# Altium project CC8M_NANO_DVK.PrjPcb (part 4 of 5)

## Sheet 18 - I2C, XBee.SchDoc: I2C, XBee
size A3; PageSetup: Record=PageOptions¦CenterHorizontal=True¦CenterVertical=True¦PrintScale=0.70¦XCorrection=1.00¦YCorrection=1.00¦PrintKind=0¦BorderSize=5000000¦LeftOffset=0¦BottomOffset=0¦Orientation=2¦PaperLength=4200¦PaperWidth=2970¦Scale=100¦PaperSource=7¦PrintQuality=600¦MediaType=1¦DitherType=10¦PaperKind=A4¦PrintScaleMode=1; Author: Juan Anzola; SheetNumber: 18; SheetTotal: 21

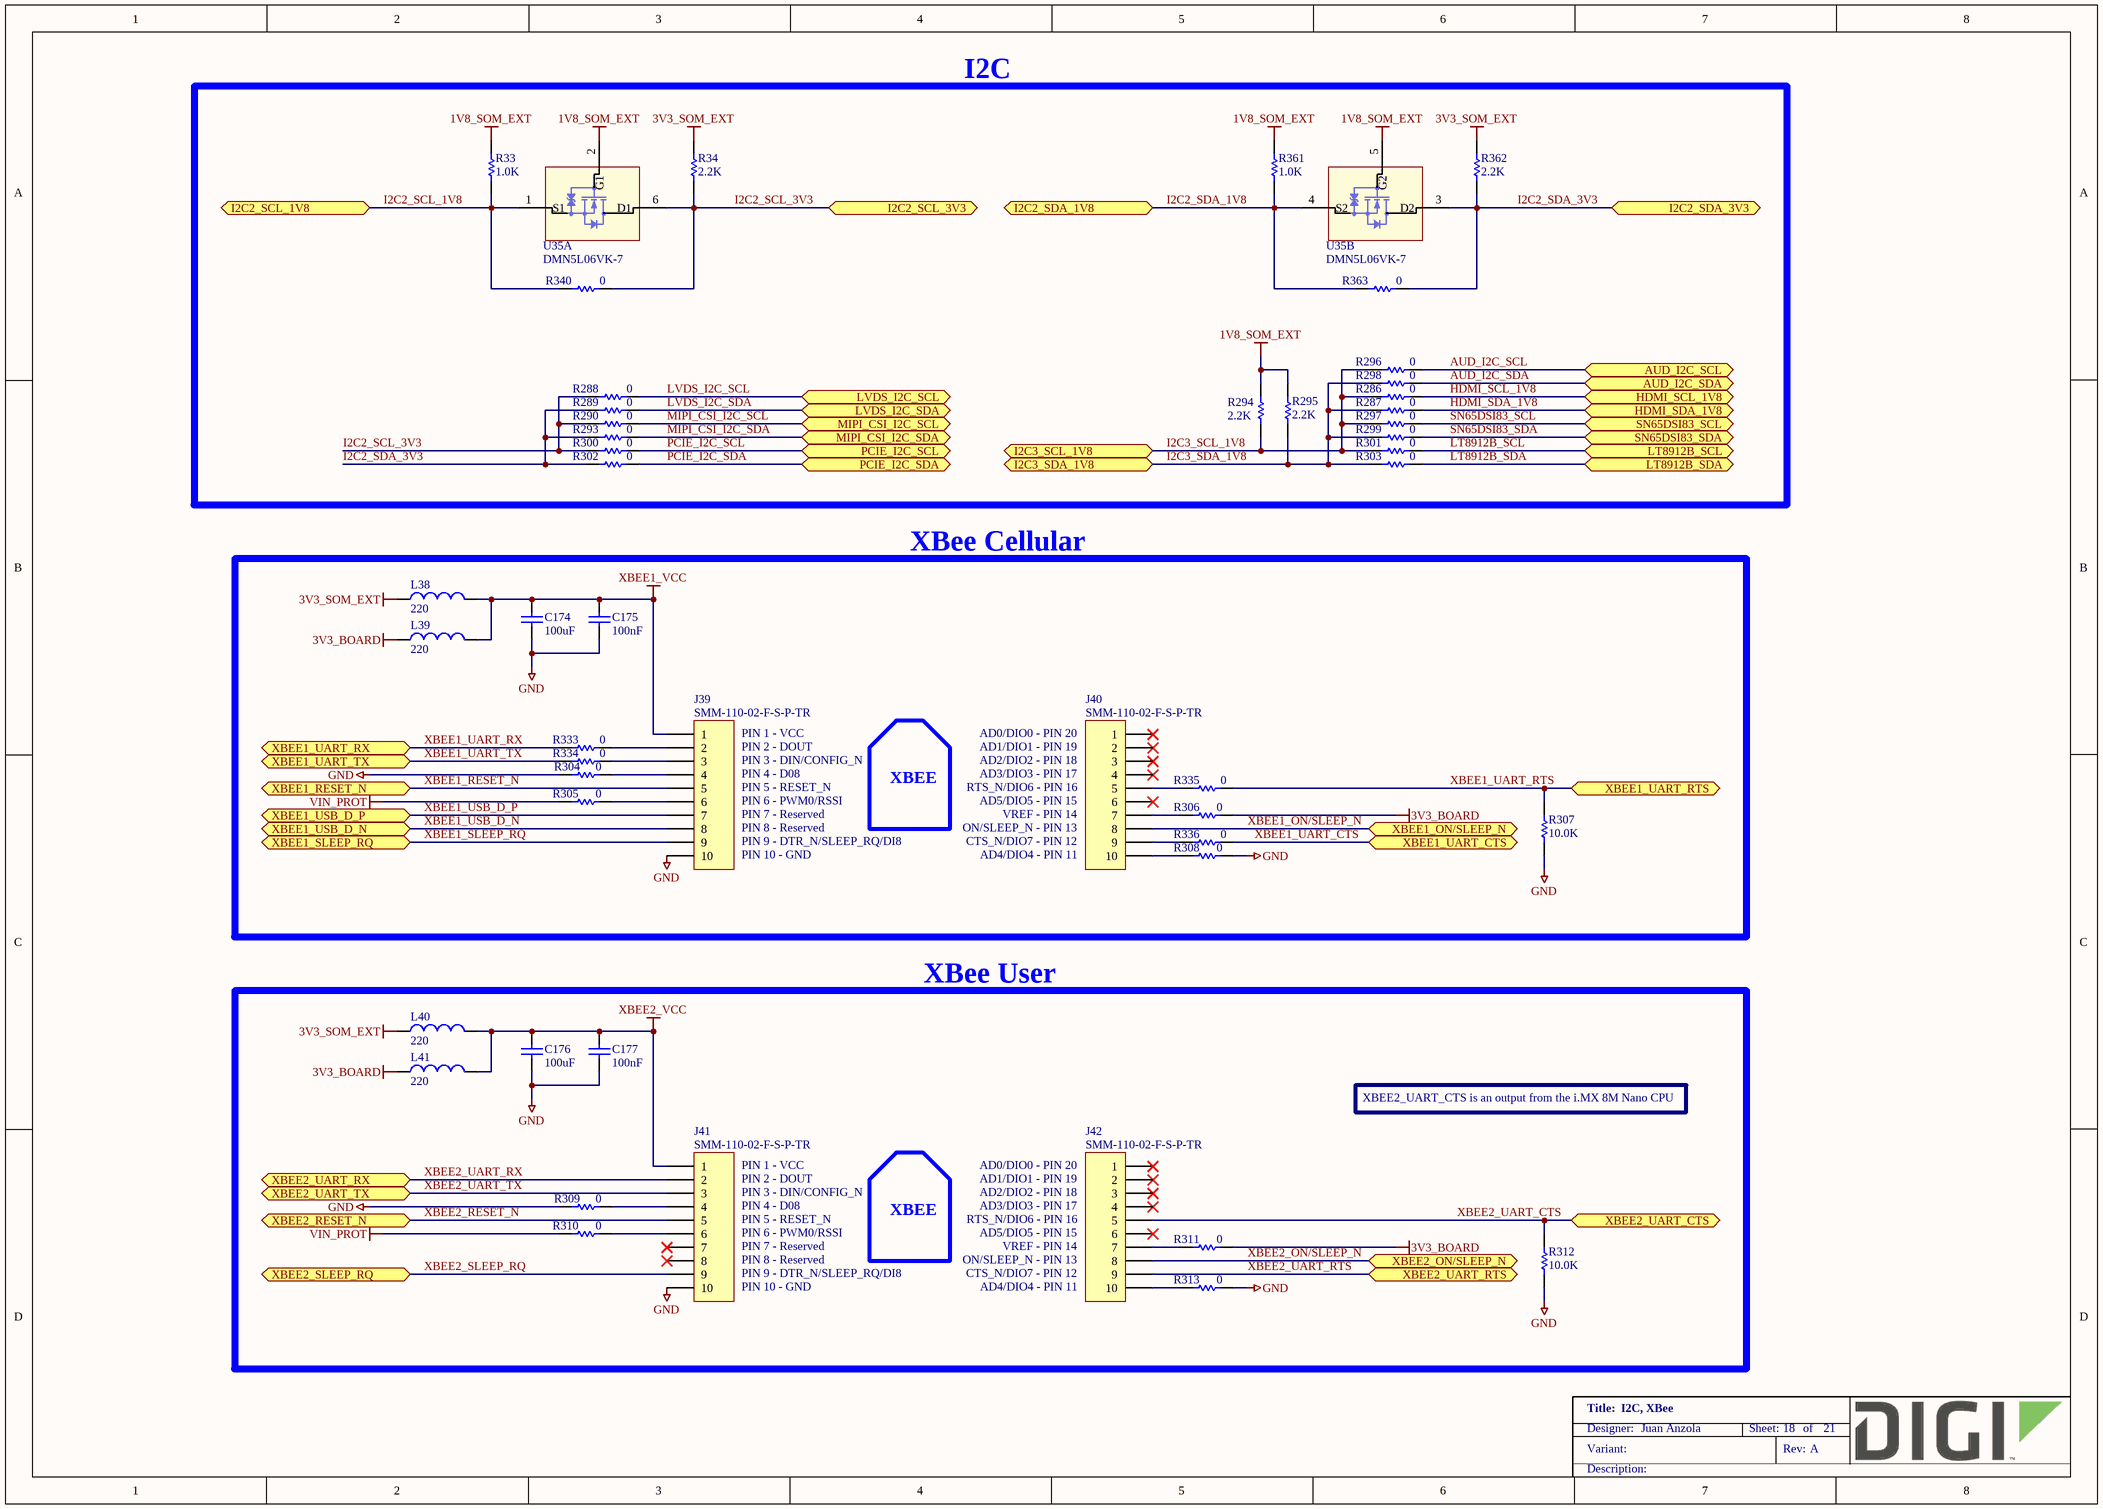
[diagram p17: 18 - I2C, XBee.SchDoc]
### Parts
C174  100uF  [CAPC3216X190N]
C175  100nF  [CAPC1005X55N]
C176  100uF  [CAPC3216X190N]
C177  100nF  [CAPC1005X55N]
J39  SMM-110-02-F-S-P-TR  [Samtec_SMM-110-02-F-S]
J40  SMM-110-02-F-S-P-TR  [Samtec_SMM-110-02-F-S]
J41  SMM-110-02-F-S-P-TR  [Samtec_SMM-110-02-F-S]
J42  SMM-110-02-F-S-P-TR  [Samtec_SMM-110-02-F-S]
L38  220  [INDC2013X110N]
L39  220  [INDC2013X110N]
L40  220  [INDC2013X110N]
L41  220  [INDC2013X110N]
R33  1.0K  [RESC1005X40N]
R34  2.2K  [RESC1005X40N]
R286  0  [RESC1005X40N]
R287  0  [RESC1005X40N]
R288  0  [RESC1005X40N]
R289  0  [RESC1005X40N]
R290  0  [RESC1005X40N]
R293  0  [RESC1005X40N]
R294  2.2K  [RESC1005X40N]
R295  2.2K  [RESC1005X40N]
R296  0  [RESC1005X40N]
R297  0  [RESC1005X40N]
R298  0  [RESC1005X40N]
R299  0  [RESC1005X40N]
R300  0  [RESC1005X40N]
R301  0  [RESC1005X40N]
R302  0  [RESC1005X40N]
R303  0  [RESC1005X40N]
R304  0  [RESC1005X40N]
R305  0  [RESC1005X40N]
R306  0  [RESC1005X40N]
R307  10.0K  [RESC1005X40N]
R308  0  [RESC1005X40N]
R309  0  [RESC1005X40N]
R310  0  [RESC1005X40N]
R311  0  [RESC1005X40N]
R312  10.0K  [RESC1005X40N]
R313  0  [RESC1005X40N]
R333  0  [RESC1005X40N]
R334  0  [RESC1005X40N]
R335  0  [RESC1005X40N]
R336  0  [RESC1005X40N]
R340  0  [RESC1005X40N]
R361  1.0K  [RESC1005X40N]
R362  2.2K  [RESC1005X40N]
R363  0  [RESC1005X40N]
U35  DMN5L06VK-7  [SOTFL50P160X60-6N]  (parts A,B of 2)

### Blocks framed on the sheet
I2C: R33 R34 R286-R290 R293-R303 R340 R361-R363 U35
XBee Cellular: C174 C175 J39 J40 L38 L39 R304-R308 R333-R336
XBee User: C176 C177 J41 J42 L40 L41 R309-R313

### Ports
AUD_I2C_SCL (bidir), AUD_I2C_SDA (bidir), HDMI_SCL_1V8 (bidir), HDMI_SDA_1V8 (bidir), I2C2_SCL_1V8 (bidir), I2C2_SCL_3V3 (bidir), I2C2_SDA_1V8 (bidir), I2C2_SDA_3V3 (bidir), I2C3_SCL_1V8 (bidir), I2C3_SDA_1V8 (bidir), LT8912B_SCL (bidir), LT8912B_SDA (bidir), LVDS_I2C_SCL (bidir), LVDS_I2C_SDA (bidir), MIPI_CSI_I2C_SCL (bidir), MIPI_CSI_I2C_SDA (bidir), PCIE_I2C_SCL (bidir), PCIE_I2C_SDA (bidir), SN65DSI83_SCL (bidir), SN65DSI83_SDA (bidir), XBEE1_ON/SLEEP_N (bidir), XBEE1_RESET_N (bidir), XBEE1_SLEEP_RQ (bidir), XBEE1_UART_CTS (bidir), XBEE1_UART_RTS (bidir), XBEE1_UART_RX (bidir), XBEE1_UART_TX (bidir), XBEE1_USB_D_N (bidir), XBEE1_USB_D_P (bidir), XBEE2_ON/SLEEP_N (bidir), XBEE2_RESET_N (bidir), XBEE2_SLEEP_RQ (bidir), XBEE2_UART_CTS (bidir), XBEE2_UART_RTS (bidir), XBEE2_UART_RX (bidir), XBEE2_UART_TX (bidir)

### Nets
1V8_SOM_EXT: R33.2 R294.2 R295.2 R361.2 U35.2(G1) U35.5(G2)
3V3_BOARD: L39.1 L41.1 R306.2 R311.2
3V3_SOM_EXT: L38.1 L40.1 R34.2 R362.2
GND: C174.1 C175.1 C176.1 C177.1 J39.10 J41.10 R304.1 R307.1 R308.2 R309.1 R312.1 R313.2
VIN_PROT: R305.1 R310.1
XBEE1_VCC: C174.2 C175.2 J39.1 L38.2 L39.2
XBEE2_VCC: C176.2 C177.2 J41.1 L40.2 L41.2
AUD_I2C_SCL: R296.2 ; port AUD_I2C_SCL
AUD_I2C_SDA: R298.2 ; port AUD_I2C_SDA
HDMI_SCL_1V8: R286.2 ; port HDMI_SCL_1V8
HDMI_SDA_1V8: R287.2 ; port HDMI_SDA_1V8
I2C2_SCL_1V8: R33.1 R340.1 U35.1(S1) ; port I2C2_SCL_1V8
I2C2_SCL_3V3: R34.1 R288.1 R290.1 R300.1 R340.2 U35.6(D1) ; port I2C2_SCL_3V3
I2C2_SDA_1V8: R361.1 R363.1 U35.4(S2) ; port I2C2_SDA_1V8
I2C2_SDA_3V3: R289.1 R293.1 R302.1 R362.1 R363.2 U35.3(D2) ; port I2C2_SDA_3V3
I2C3_SCL_1V8: R286.1 R294.1 R296.1 R297.1 R301.1 ; port I2C3_SCL_1V8
I2C3_SDA_1V8: R287.1 R295.1 R298.1 R299.1 R303.1 ; port I2C3_SDA_1V8
LT8912B_SCL: R301.2 ; port LT8912B_SCL
LT8912B_SDA: R303.2 ; port LT8912B_SDA
LVDS_I2C_SCL: R288.2 ; port LVDS_I2C_SCL
LVDS_I2C_SDA: R289.2 ; port LVDS_I2C_SDA
MIPI_CSI_I2C_SCL: R290.2 ; port MIPI_CSI_I2C_SCL
MIPI_CSI_I2C_SDA: R293.2 ; port MIPI_CSI_I2C_SDA
PCIE_I2C_SCL: R300.2 ; port PCIE_I2C_SCL
PCIE_I2C_SDA: R302.2 ; port PCIE_I2C_SDA
SN65DSI83_SCL: R297.2 ; port SN65DSI83_SCL
SN65DSI83_SDA: R299.2 ; port SN65DSI83_SDA
XBEE1_ON/SLEEP_N: J40.8 ; port XBEE1_ON/SLEEP_N
XBEE1_RESET_N: J39.5 ; port XBEE1_RESET_N
XBEE1_SLEEP_RQ: J39.9 ; port XBEE1_SLEEP_RQ
XBEE1_UART_CTS: R336.2 ; port XBEE1_UART_CTS
XBEE1_UART_RTS: R307.2 R335.2 ; port XBEE1_UART_RTS
XBEE1_UART_RX: R333.1 ; port XBEE1_UART_RX
XBEE1_UART_TX: R334.1 ; port XBEE1_UART_TX
XBEE1_USB_D_N: J39.8 ; port XBEE1_USB_D_N
XBEE1_USB_D_P: J39.7 ; port XBEE1_USB_D_P
XBEE2_ON/SLEEP_N: J42.8 ; port XBEE2_ON/SLEEP_N
XBEE2_RESET_N: J41.5 ; port XBEE2_RESET_N
XBEE2_SLEEP_RQ: J41.9 ; port XBEE2_SLEEP_RQ
XBEE2_UART_CTS: J42.5 R312.2 ; port XBEE2_UART_CTS
XBEE2_UART_RTS: J42.9 ; port XBEE2_UART_RTS
XBEE2_UART_RX: J41.2 ; port XBEE2_UART_RX
XBEE2_UART_TX: J41.3 ; port XBEE2_UART_TX
NetJ39_2: J39.2 R333.2
NetJ39_3: J39.3 R334.2
NetJ39_4: J39.4 R304.2
NetJ39_6: J39.6 R305.2
NetJ40_5: J40.5 R335.1
NetJ40_7: J40.7 R306.1
NetJ40_9: J40.9 R336.1
NetJ40_10: J40.10 R308.1
NetJ41_4: J41.4 R309.2
NetJ41_6: J41.6 R310.2
NetJ42_7: J42.7 R311.1
NetJ42_10: J42.10 R313.1

Not connected (* = marked no-connect by the designer): J40 1* 2* 3* 4* 6*; J41 7* 8*; J42 1* 2* 3* 4* 6*

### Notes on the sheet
- (near J39) PIN 1 - VCC
- (near J39) PIN 2 - DOUT
- (near J39) PIN 3 - DIN/CONFIG_N
- (near J39) PIN 4 - D08
- XBEE
- (near J40) AD0/DIO0 - PIN 20
- (near J40) AD1/DIO1 - PIN 19
- (near J40) AD2/DIO2 - PIN 18
- (near J40) AD3/DIO3 - PIN 17
- (near J39) PIN 5 - RESET_N
- (near J39) PIN 6 - PWM0/RSSI
- (near J39) PIN 7 - Reserved
- (near J39) PIN 8 - Reserved
- (near J39) PIN 9 - DTR_N/SLEEP_RQ/DI8
- (near J39) PIN 10 - GND
- (near J40) RTS_N/DIO6 - PIN 16
- (near J40) AD5/DIO5 - PIN 15
- (near J40) VREF - PIN 14
- (near J40) ON/SLEEP_N - PIN 13
- (near J40) CTS_N/DIO7 - PIN 12
- (near J40) AD4/DIO4 - PIN 11
- XBEE2_UART_CTS is an output from the i.MX 8M Nano CPU
- (near J41) PIN 1 - VCC
- (near J41) PIN 2 - DOUT
- (near J42) AD0/DIO0 - PIN 20
- (near J42) AD1/DIO1 - PIN 19
- (near J41) PIN 3 - DIN/CONFIG_N
- (near J41) PIN 4 - D08
- (near J41) PIN 5 - RESET_N
- (near J41) PIN 6 - PWM0/RSSI
- (near J41) PIN 7 - Reserved
- (near J41) PIN 8 - Reserved
- (near J42) AD2/DIO2 - PIN 18
- (near J42) AD3/DIO3 - PIN 17
- (near J42) RTS_N/DIO6 - PIN 16
- (near J42) AD5/DIO5 - PIN 15
- (near J42) VREF - PIN 14
- (near J42) ON/SLEEP_N - PIN 13
- (near J41) PIN 9 - DTR_N/SLEEP_RQ/DI8
- (near J41) PIN 10 - GND
- (near J42) CTS_N/DIO7 - PIN 12
- (near J42) AD4/DIO4 - PIN 11

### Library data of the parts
C174 C176 = 1000566: CAP CER 100UF 10V 20% X5R 1206; Part_Type: Capacitor; Manufacturer: TDK Corporation; Manufacturer_Part_Number: C3216X5R1A107M; Digi_PN: 14050666; Component_Life_Cycle_State: Reviewed; Area: 7.47; Project: GSM Cell PCB
C175 C177 = 1000006: CAP 100nF 16V 10% X7R 0402; Part_Type: Capacitor; Manufacturer: Murata; Manufacturer_Part_Number: GRM155R71C104KA88D; Component_Life_Cycle_State: CAD Reviewed; Area: 0.95; Project: KITT; Tolerance: 10; Digi_PN: 14050552
J39-J42 = 1001495: CONN RCPT 2MM 10POS SMD; Part_Type: Connector; Manufacturer: Samtec; Digi_PN: 19050036; Component_Life_Cycle_State: Reviewed; Area: 105; Project: CCWMX6_SBC board
L38-L41 = 1001174: FERRITE BEAD 220 OHM 2.0A 0805; Manufacturer: Wurth Electronics Inc; Manufacturer_Part_Number: 742792022; Digi_PN: 21000146; Component_Life_Cycle_State: Reviewed; Area: 4.24; Project: CCWMX6_SBC board
R33 R361 = 1000079: RES 1.00K OHM 1/10W 1% 0402 SMD; Part_Type: Resistor; Manufacturer: Panasonic - ECG; Manufacturer_Part_Number: ERJ-2RKF1001X; Digi_PN: 13051085; Component_Life_Cycle_State: Proven; Area: 0,95; Project: Adjustable Foundation; Power_WV_SRF: 10
R34 R362 = 1001156: RES 2.20K OHM 1/16W 1% 0402 SMD; Part_Type: Resistor; Manufacturer: Yageo; Manufacturer_Part_Number: RC0402FR-072K2L; Note: 13051099 = Digi No. for GE WDNU; Digi_PN: 13050699; Component_Life_Cycle_State: Reviewed; Area: 0,95
R286-R290 R293 R296-R306 R308-R311 R313 = 1000076: RES 0.0 OHM 1/10W 0402 SMD; Part_Type: Resistor; Manufacturer: Panasonic - ECG; Manufacturer_Part_Number: ERJ-2GE0R00X; Component_Life_Cycle_State: Proven; Area: 0.95; Project: Adjustable Foundation; Power_WV_SRF: 10; Digi_PN: 13050387
R294 R295 = 1001156: RES 2.20K OHM 1/16W 1% 0402 SMD; Part_Type: Resistor; Manufacturer: Yageo; Manufacturer_Part_Number: RC0402FR-072K2L; Digi_PN: 13050699; Component_Life_Cycle_State: Reviewed; Area: 0.95; Project: CCWMX6_SBC board; Note: 13051099 = Digi No. for GE WDNU
R307 R312 = 1000537: RES 10.0K OHM 1/10W 1% 0402 SMD; Part_Type: Resistor; Manufacturer: Panasonic - ECG; Manufacturer_Part_Number: ERJ-2RKF1002X; Component_Life_Cycle_State: CAD Reviewed; Area: 0.95; Project: KITT; Power_WV_SRF: 100; Digi_PN: 13051084
R333-R336 R340 R363 = 1000076: RES 0.0 OHM 1/10W 0402 SMD; Part_Type: Resistor; Manufacturer: Panasonic - ECG; Manufacturer_Part_Number: ERJ-2GE0R00X; Digi_PN: 13050387; Component_Life_Cycle_State: Proven; Area: 0,95; Power_WV_SRF: 10
U35 = 1002493: MOSFET 2N-CH 30V 0.1A ES6; Part_Type: Transistor; Manufacturer: Diodes, Inc.; Digi_PN: 17000134; Component_Life_Cycle_State: Reviewed; Area: 4,88

## Sheet 19 - Expansion connectors, User LEDs, RF signals.SchDoc: Expansion connectors, User LEDs, RF signals
size A3; PageSetup: Record=PageOptions¦CenterHorizontal=True¦CenterVertical=True¦PrintScale=0.70¦XCorrection=1.00¦YCorrection=1.00¦PrintKind=0¦BorderSize=5000000¦LeftOffset=0¦BottomOffset=0¦Orientation=2¦PaperLength=4200¦PaperWidth=2970¦Scale=100¦PaperSource=7¦PrintQuality=600¦MediaType=1¦DitherType=10¦PaperKind=A4¦PrintScaleMode=1; Author: Juan Anzola; SheetNumber: 19; SheetTotal: 21

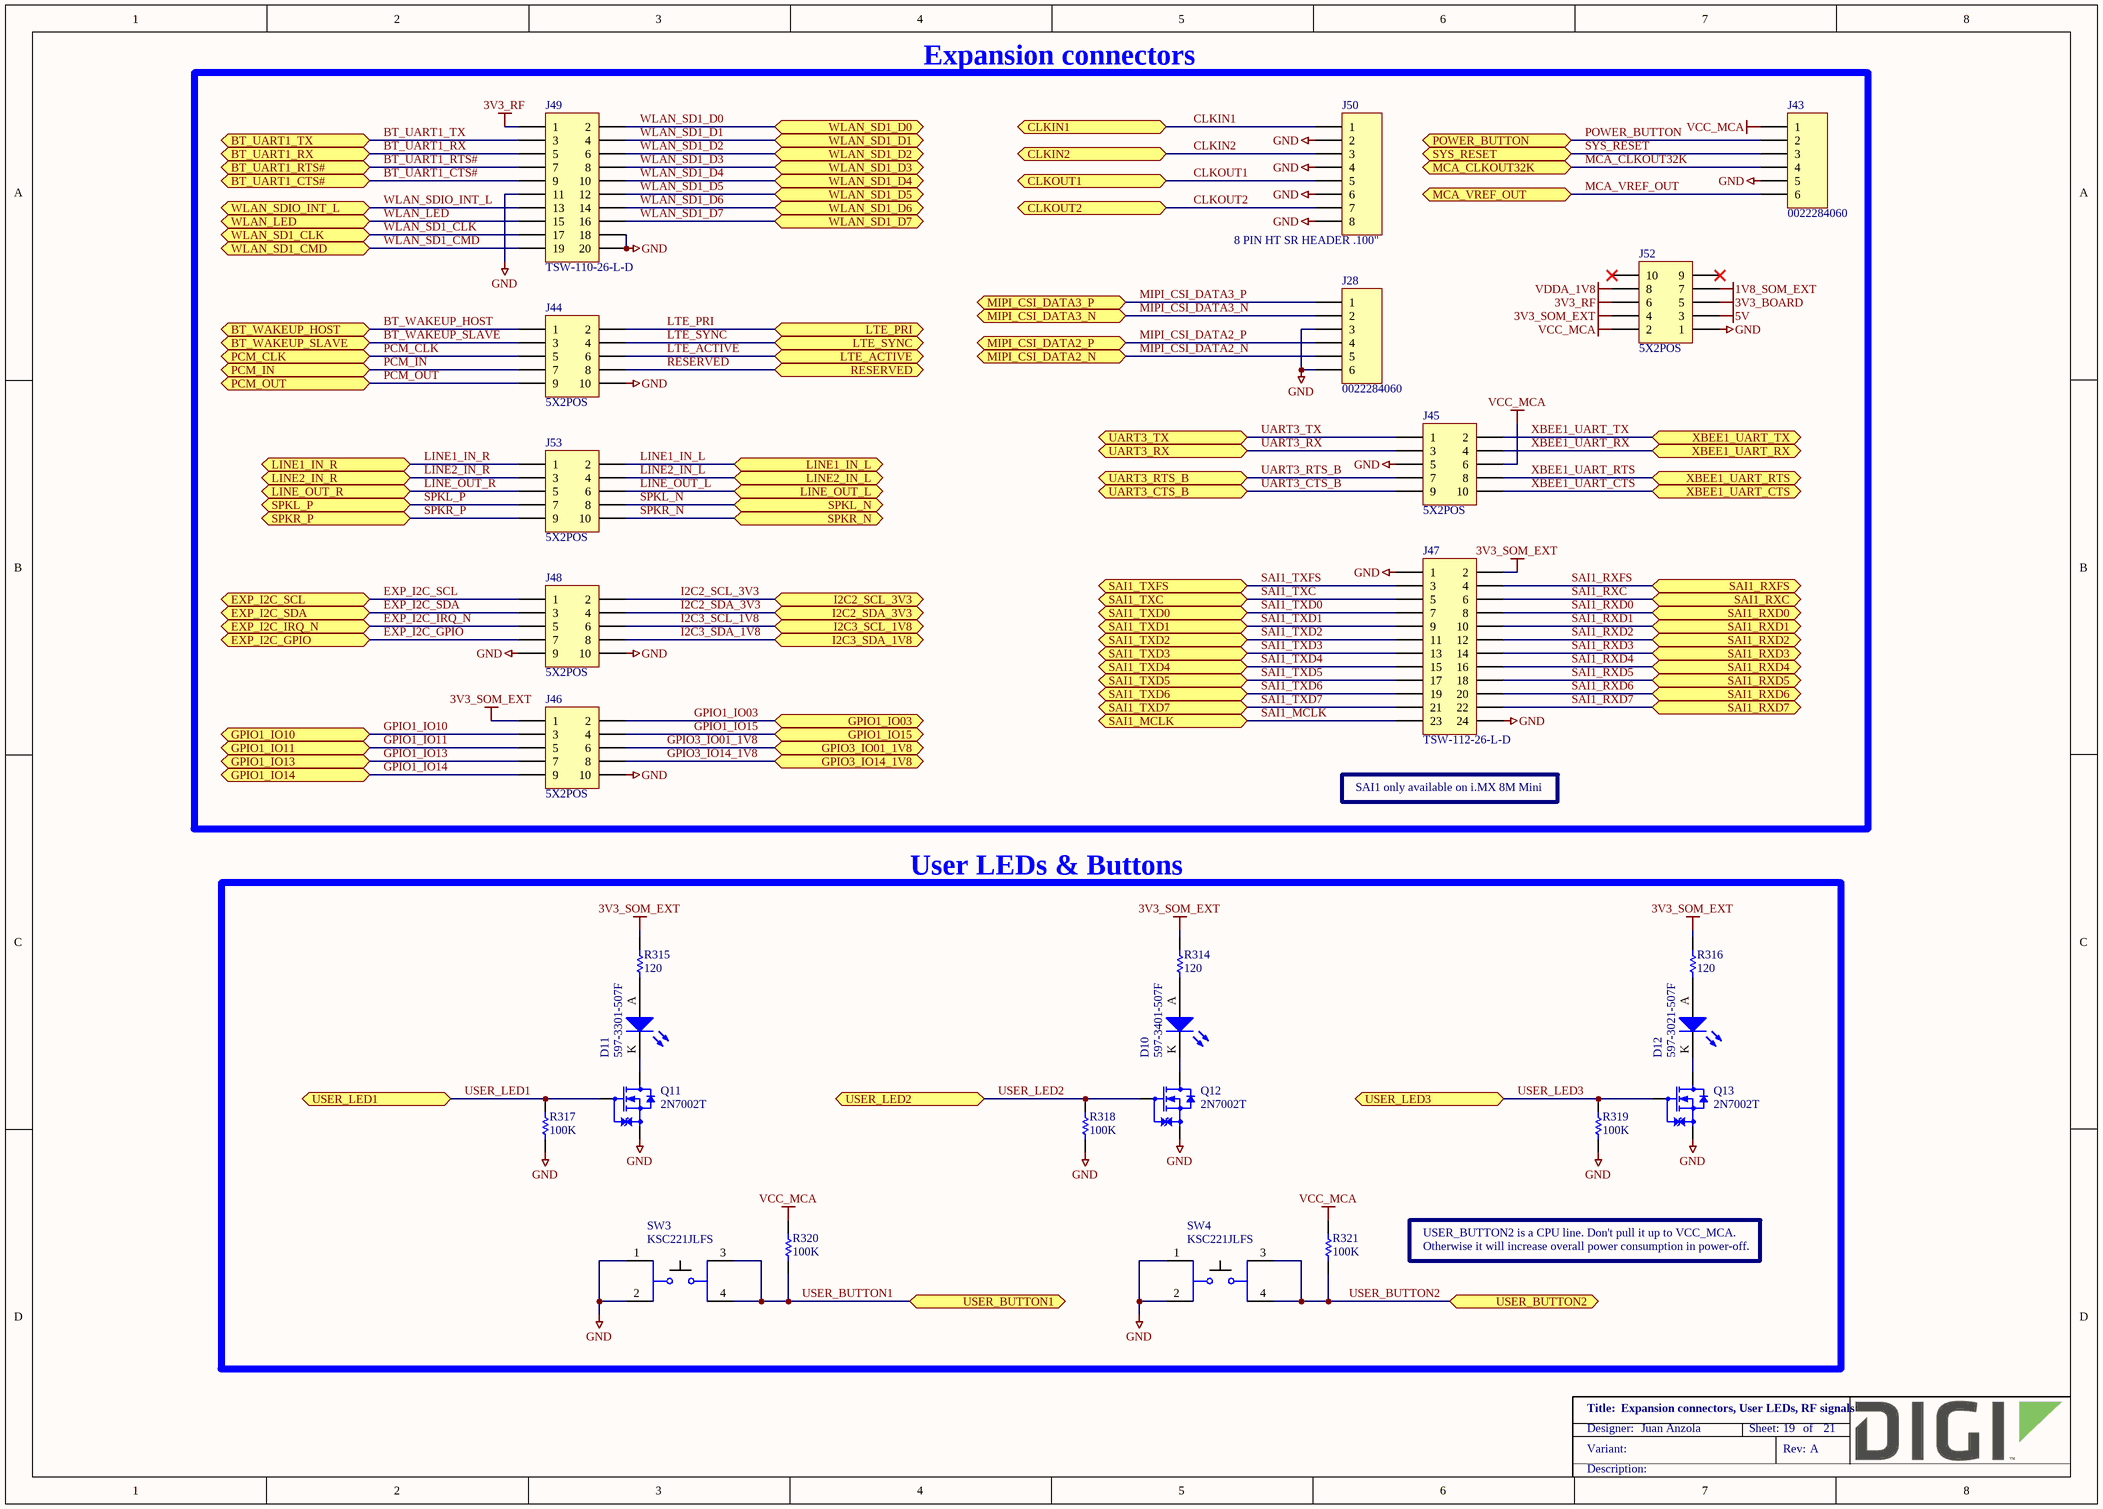
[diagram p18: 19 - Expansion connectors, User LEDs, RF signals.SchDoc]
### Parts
D10  597-3401-507F  [LEDM3020X130N_YELLOW]
D11  597-3301-507F  [LEDM3020X130N_GREEN]
D12  597-3021-507F  [LEDM3020X130N]
J28  0022284060  [MOLEX_0022284060]
J43  0022284060  [MOLEX_0022284060]
J44  5X2POS  [MOLEX_87914-1016]
J45  5X2POS  [MOLEX_87914-1016]
J46  5X2POS  [MOLEX_87914-1016]
J47  TSW-112-26-L-D  [SAMTEC_TSW-112-26-L-D]
J48  5X2POS  [MOLEX_87914-1016]
J49  TSW-110-26-L-D  [SAMTEC_TSW-110-26-L-D]
J50  8 PIN HT SR HEADER .100"  [SAMTEC_TSW-108-07-X-S]
J52  5X2POS  [MOLEX_87914-1016]
J53  5X2POS  [MOLEX_87914-1016]
Q11  2N7002T  [SOTFL50P160X80_GSD-3N]
Q12  2N7002T  [SOTFL50P160X80_GSD-3N]
Q13  2N7002T  [SOTFL50P160X80_GSD-3N]
R314  120  [RESC1005X40N]
R315  120  [RESC1005X40N]
R316  120  [RESC1005X40N]
R317  100K  [RESC1005X40N]
R318  100K  [RESC1005X40N]
R319  100K  [RESC1005X40N]
R320  100K  [RESC1005X40N]
R321  100K  [RESC1005X40N]
SW3  KSC221JLFS  [SW_KSC221J]
SW4  KSC221JLFS  [SW_KSC221J]

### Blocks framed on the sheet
Expansion connectors: J28 J43-J50 J52 J53
User LEDs & Buttons: D10-D12 Q11-Q13 R314-R321 SW3 SW4

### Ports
BT_UART1_CTS# (bidir), BT_UART1_RTS# (bidir), BT_UART1_RX (bidir), BT_UART1_TX (bidir), BT_WAKEUP_HOST (bidir), BT_WAKEUP_SLAVE (bidir), CLKIN1 (bidir), CLKIN2 (bidir), CLKOUT1 (bidir), CLKOUT2 (bidir), EXP_I2C_GPIO (bidir), EXP_I2C_IRQ_N (bidir), EXP_I2C_SCL (bidir), EXP_I2C_SDA (bidir), GPIO1_IO03 (bidir), GPIO1_IO10 (bidir), GPIO1_IO11 (bidir), GPIO1_IO13 (bidir), GPIO1_IO14 (bidir), GPIO1_IO15 (bidir), GPIO3_IO01_1V8 (bidir), GPIO3_IO14_1V8 (bidir), I2C2_SCL_3V3 (bidir), I2C2_SDA_3V3 (bidir), I2C3_SCL_1V8 (bidir), I2C3_SDA_1V8 (bidir), LINE1_IN_L (bidir), LINE1_IN_R (bidir), LINE2_IN_L (bidir), LINE2_IN_R (bidir), LINE_OUT_L (bidir), LINE_OUT_R (bidir), LTE_ACTIVE (bidir), LTE_PRI (bidir), LTE_SYNC (bidir), MCA_CLKOUT32K (bidir), MCA_VREF_OUT (bidir), MIPI_CSI_DATA2_N (bidir), MIPI_CSI_DATA2_P (bidir), MIPI_CSI_DATA3_N (bidir), MIPI_CSI_DATA3_P (bidir), PCM_CLK (bidir), PCM_IN (bidir), PCM_OUT (bidir), POWER_BUTTON (bidir), RESERVED (bidir), SAI1_MCLK (bidir), SAI1_RXC (bidir), SAI1_RXD0 (bidir), SAI1_RXD1 (bidir), SAI1_RXD2 (bidir), SAI1_RXD3 (bidir), SAI1_RXD4 (bidir), SAI1_RXD5 (bidir), SAI1_RXD6 (bidir), SAI1_RXD7 (bidir), SAI1_RXFS (bidir), SAI1_TXC (bidir), SAI1_TXD0 (bidir), SAI1_TXD1 (bidir), SAI1_TXD2 (bidir), SAI1_TXD3 (bidir), SAI1_TXD4 (bidir), SAI1_TXD5 (bidir), SAI1_TXD6 (bidir), SAI1_TXD7 (bidir), SAI1_TXFS (bidir), SPKL_N (bidir), SPKL_P (bidir), SPKR_N (bidir), SPKR_P (bidir), SYS_RESET (bidir), UART3_CTS_B (bidir), UART3_RTS_B (bidir), UART3_RX (bidir), UART3_TX (bidir), USER_BUTTON1 (bidir), USER_BUTTON2 (bidir), USER_LED1 (bidir), USER_LED2 (bidir), USER_LED3 (bidir), WLAN_LED (bidir), WLAN_SD1_CLK (bidir), WLAN_SD1_CMD (bidir), WLAN_SD1_D0 (bidir), WLAN_SD1_D1 (bidir), WLAN_SD1_D2 (bidir), WLAN_SD1_D3 (bidir), WLAN_SD1_D4 (bidir), WLAN_SD1_D5 (bidir), WLAN_SD1_D6 (bidir), WLAN_SD1_D7 (bidir), WLAN_SDIO_INT_L (bidir), XBEE1_UART_CTS (bidir), XBEE1_UART_RTS (bidir), XBEE1_UART_RX (bidir), XBEE1_UART_TX (bidir)

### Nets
1V8_SOM_EXT: J52.7
3V3_BOARD: J52.5
3V3_RF: J49.1 J52.6
3V3_SOM_EXT: J46.1 J47.2 J52.4 R314.2 R315.2 R316.2
5V: J52.3
GND: J28.3 J28.6 J43.5 J44.10 J45.5 J46.10 J47.1 J47.24 J48.9 J48.10 J49.11 J49.18 J49.20 J50.2 J50.4 J50.6 J50.8 J52.1 Q11.S Q12.S Q13.S R317.2 R318.2 R319.2 SW3.1 SW3.2 SW4.1 SW4.2
VCC_MCA: J43.1 J45.6 J52.2 R320.2 R321.2
VDDA_1V8: J52.8
BT_UART1_CTS#: J49.9 ; port BT_UART1_CTS#
BT_UART1_RTS#: J49.7 ; port BT_UART1_RTS#
BT_UART1_RX: J49.5 ; port BT_UART1_RX
BT_UART1_TX: J49.3 ; port BT_UART1_TX
BT_WAKEUP_HOST: J44.1 ; port BT_WAKEUP_HOST
BT_WAKEUP_SLAVE: J44.3 ; port BT_WAKEUP_SLAVE
CLKIN1: J50.1 ; port CLKIN1
CLKIN2: J50.3 ; port CLKIN2
CLKOUT1: J50.5 ; port CLKOUT1
CLKOUT2: J50.7 ; port CLKOUT2
EXP_I2C_GPIO: J48.7 ; port EXP_I2C_GPIO
EXP_I2C_IRQ_N: J48.5 ; port EXP_I2C_IRQ_N
EXP_I2C_SCL: J48.1 ; port EXP_I2C_SCL
EXP_I2C_SDA: J48.3 ; port EXP_I2C_SDA
GPIO1_IO03: J46.2 ; port GPIO1_IO03
GPIO1_IO10: J46.3 ; port GPIO1_IO10
GPIO1_IO11: J46.5 ; port GPIO1_IO11
GPIO1_IO13: J46.7 ; port GPIO1_IO13
GPIO1_IO14: J46.9 ; port GPIO1_IO14
GPIO1_IO15: J46.4 ; port GPIO1_IO15
GPIO3_IO01_1V8: J46.6 ; port GPIO3_IO01_1V8
GPIO3_IO14_1V8: J46.8 ; port GPIO3_IO14_1V8
I2C2_SCL_3V3: J48.2 ; port I2C2_SCL_3V3
I2C2_SDA_3V3: J48.4 ; port I2C2_SDA_3V3
I2C3_SCL_1V8: J48.6 ; port I2C3_SCL_1V8
I2C3_SDA_1V8: J48.8 ; port I2C3_SDA_1V8
LINE1_IN_L: J53.2 ; port LINE1_IN_L
LINE1_IN_R: J53.1 ; port LINE1_IN_R
LINE2_IN_L: J53.4 ; port LINE2_IN_L
LINE2_IN_R: J53.3 ; port LINE2_IN_R
LINE_OUT_L: J53.6 ; port LINE_OUT_L
LINE_OUT_R: J53.5 ; port LINE_OUT_R
LTE_ACTIVE: J44.6 ; port LTE_ACTIVE
LTE_PRI: J44.2 ; port LTE_PRI
LTE_SYNC: J44.4 ; port LTE_SYNC
MCA_CLKOUT32K: J43.4 ; port MCA_CLKOUT32K
MCA_VREF_OUT: J43.6 ; port MCA_VREF_OUT
MIPI_CSI_DATA2_N: J28.5 ; port MIPI_CSI_DATA2_N
MIPI_CSI_DATA2_P: J28.4 ; port MIPI_CSI_DATA2_P
MIPI_CSI_DATA3_N: J28.2 ; port MIPI_CSI_DATA3_N
MIPI_CSI_DATA3_P: J28.1 ; port MIPI_CSI_DATA3_P
PCM_CLK: J44.5 ; port PCM_CLK
PCM_IN: J44.7 ; port PCM_IN
PCM_OUT: J44.9 ; port PCM_OUT
POWER_BUTTON: J43.2 ; port POWER_BUTTON
RESERVED: J44.8 ; port RESERVED
SAI1_MCLK: J47.23 ; port SAI1_MCLK
SAI1_RXC: J47.6 ; port SAI1_RXC
SAI1_RXD0: J47.8 ; port SAI1_RXD0
SAI1_RXD1: J47.10 ; port SAI1_RXD1
SAI1_RXD2: J47.12 ; port SAI1_RXD2
SAI1_RXD3: J47.14 ; port SAI1_RXD3
SAI1_RXD4: J47.16 ; port SAI1_RXD4
SAI1_RXD5: J47.18 ; port SAI1_RXD5
SAI1_RXD6: J47.20 ; port SAI1_RXD6
SAI1_RXD7: J47.22 ; port SAI1_RXD7
SAI1_RXFS: J47.4 ; port SAI1_RXFS
SAI1_TXC: J47.5 ; port SAI1_TXC
SAI1_TXD0: J47.7 ; port SAI1_TXD0
SAI1_TXD1: J47.9 ; port SAI1_TXD1
SAI1_TXD2: J47.11 ; port SAI1_TXD2
SAI1_TXD3: J47.13 ; port SAI1_TXD3
SAI1_TXD4: J47.15 ; port SAI1_TXD4
SAI1_TXD5: J47.17 ; port SAI1_TXD5
SAI1_TXD6: J47.19 ; port SAI1_TXD6
SAI1_TXD7: J47.21 ; port SAI1_TXD7
SAI1_TXFS: J47.3 ; port SAI1_TXFS
SPKL_N: J53.8 ; port SPKL_N
SPKL_P: J53.7 ; port SPKL_P
SPKR_N: J53.10 ; port SPKR_N
SPKR_P: J53.9 ; port SPKR_P
SYS_RESET: J43.3 ; port SYS_RESET
UART3_CTS_B: J45.9 ; port UART3_CTS_B
UART3_RTS_B: J45.7 ; port UART3_RTS_B
UART3_RX: J45.3 ; port UART3_RX
UART3_TX: J45.1 ; port UART3_TX
USER_BUTTON1: R320.1 SW3.3 SW3.4 ; port USER_BUTTON1
USER_BUTTON2: R321.1 SW4.3 SW4.4 ; port USER_BUTTON2
USER_LED1: Q11.G R317.1 ; port USER_LED1
USER_LED2: Q12.G R318.1 ; port USER_LED2
USER_LED3: Q13.G R319.1 ; port USER_LED3
WLAN_LED: J49.15 ; port WLAN_LED
WLAN_SD1_CLK: J49.17 ; port WLAN_SD1_CLK
WLAN_SD1_CMD: J49.19 ; port WLAN_SD1_CMD
WLAN_SD1_D0: J49.2 ; port WLAN_SD1_D0
WLAN_SD1_D1: J49.4 ; port WLAN_SD1_D1
WLAN_SD1_D2: J49.6 ; port WLAN_SD1_D2
WLAN_SD1_D3: J49.8 ; port WLAN_SD1_D3
WLAN_SD1_D4: J49.10 ; port WLAN_SD1_D4
WLAN_SD1_D5: J49.12 ; port WLAN_SD1_D5
WLAN_SD1_D6: J49.14 ; port WLAN_SD1_D6
WLAN_SD1_D7: J49.16 ; port WLAN_SD1_D7
WLAN_SDIO_INT_L: J49.13 ; port WLAN_SDIO_INT_L
XBEE1_UART_CTS: J45.10 ; port XBEE1_UART_CTS
XBEE1_UART_RTS: J45.8 ; port XBEE1_UART_RTS
XBEE1_UART_RX: J45.4 ; port XBEE1_UART_RX
XBEE1_UART_TX: J45.2 ; port XBEE1_UART_TX
NetD10_A: D10.A R314.1
NetD10_K: D10.K Q12.D
NetD11_A: D11.A R315.1
NetD11_K: D11.K Q11.D
NetD12_A: D12.A R316.1
NetD12_K: D12.K Q13.D

Not connected (* = marked no-connect by the designer): J52 9* 10*

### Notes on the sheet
- SAI1 only available on i.MX 8M Mini
- USER_BUTTON2 is a CPU line. Don't pull it up to VCC_MCA.
- Otherwise it will increase overall power consumption in power-off.

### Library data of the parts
D10 = 1001188: LED YELLOW 588NM 1208 SMD; Manufacturer: Dialight; Note: 17050842 = Digi No. for GE WDNU; Digi_PN: 17050387; Component_Life_Cycle_State: Reviewed; Area: 6
D11 = 1001189: LED GREEN 573NM 1208 SMD; Manufacturer: Dialight; Note: 17050846 = Digi PN for GE WDNU II; Digi_PN: 17050183; Component_Life_Cycle_State: Reviewed; Area: 6
D12 = 1001190: LED RED 653NM 20MA 1208 SMD; Manufacturer: Dialight; Digi_PN: 17050184; Component_Life_Cycle_State: Reviewed; Area: 6
J28 J43 = 1002721: CONN HEADER VERT 6POS 2.54MM; Part_Type: Connector; Manufacturer: Molex; Digi_PN: 0790004; Component_Life_Cycle_State: Reviewed; Area: 42,49
J44-J46 J48 J52 J53 = 1001335: CONN HEADER 10POS DL VERT T/H; Part_Type: Connector; Manufacturer: Molex; Manufacturer_Part_Number: 87914-1016; Note: Check symbol pin-out upon reactivation; Digi_PN: 18000793; Component_Life_Cycle_State: Abandoned; Area: 63,5
J47 = 1002752: CONN HEADER VERT 24POS 2.54MM; Part_Type: Connector; Manufacturer: Samtec; Digi_PN: 18000795; Component_Life_Cycle_State: Created; Area: 179,25
J49 = 1002751: CONN HEADER VERT 20POS 2.54MM; Part_Type: Connector; Manufacturer: Samtec; Digi_PN: 01730020; Component_Life_Cycle_State: Created; Area: 150,08
J50 = 1000191: CONN HEADER 8POS .100" SNGL; Part_Type: Connector; Manufacturer: Samtec; Manufacturer_Part_Number: TSW-108-07-G-S; Component_Life_Cycle_State: Reviewed; Area: 51,61; Digi_PN: 18000792
Q11-Q13 = 1000715: MOSFET N-CH 60V 115MA SOT-523F; Part_Type: Transistor; Manufacturer: Fairchild Semiconductor; Digi_PN: 17050797; Component_Life_Cycle_State: CAD Reviewed; Area: 3.06; Project: SmartMeter2; Note: 17050841 = Digi No. for GE WDNU
R314-R316 = 1001158: RES 120 OHM 1/16W 1% 0402 SMD; Part_Type: Resistor; Manufacturer: Yageo; Manufacturer_Part_Number: RC0402FR-07120RL; Note: 13051102 = Digi No. for GE WDNU; Digi_PN: 13050832; Component_Life_Cycle_State: Reviewed; Area: 0,95; Project: CCWMX6_SBC board
R317-R319 = 1000480: RES 100K OHM 1/10W 1% 0402 SMD; Part_Type: Resistor; Manufacturer: Panasonic - ECG; Manufacturer_Part_Number: ERJ-2RKF1003X; Digi_PN: 13051063; Component_Life_Cycle_State: CAD Reviewed; Area: 0.95; Project: KITT; Power_WV_SRF: 100
R320 R321 = 1000480: RES 100K OHM 1/10W 1% 0402 SMD; Part_Type: Resistor; Manufacturer: Panasonic - ECG; Manufacturer_Part_Number: ERJ-2RKF1003X; Digi_PN: 13051063; Component_Life_Cycle_State: CAD Reviewed; Area: 0,95; Project: KITT; Power_WV_SRF: 100
SW3 SW4 = 1001124: SWITCH TACTILE SPST-NO 0.05A 32V; Manufacturer: ITT; Digi_PN: 22000059; Component_Life_Cycle_State: Reviewed; Area: 37; Project: CCWMX6_SBC board; Note: 22000295 = Digi No. for GE WDNU

## Sheet 20 - GPIO Table, I2C Addresses.SchDoc: GPIO Table, I2C Addresses
size A3; PageSetup: Record=PageOptions¦CenterHorizontal=True¦CenterVertical=True¦PrintScale=1.01¦XCorrection=1.00¦YCorrection=1.00¦PrintKind=0¦BorderSize=5000000¦LeftOffset=0¦BottomOffset=0¦Orientation=2¦PaperLength=4200¦PaperWidth=2970¦Scale=100¦PaperSource=15¦PrintQuality=600¦MediaType=1¦DitherType=10¦PrintScaleMode=1¦PaperKind=A3¦PaperIndex=8; Author: Juan Anzola; SheetNumber: 20; SheetTotal: 21

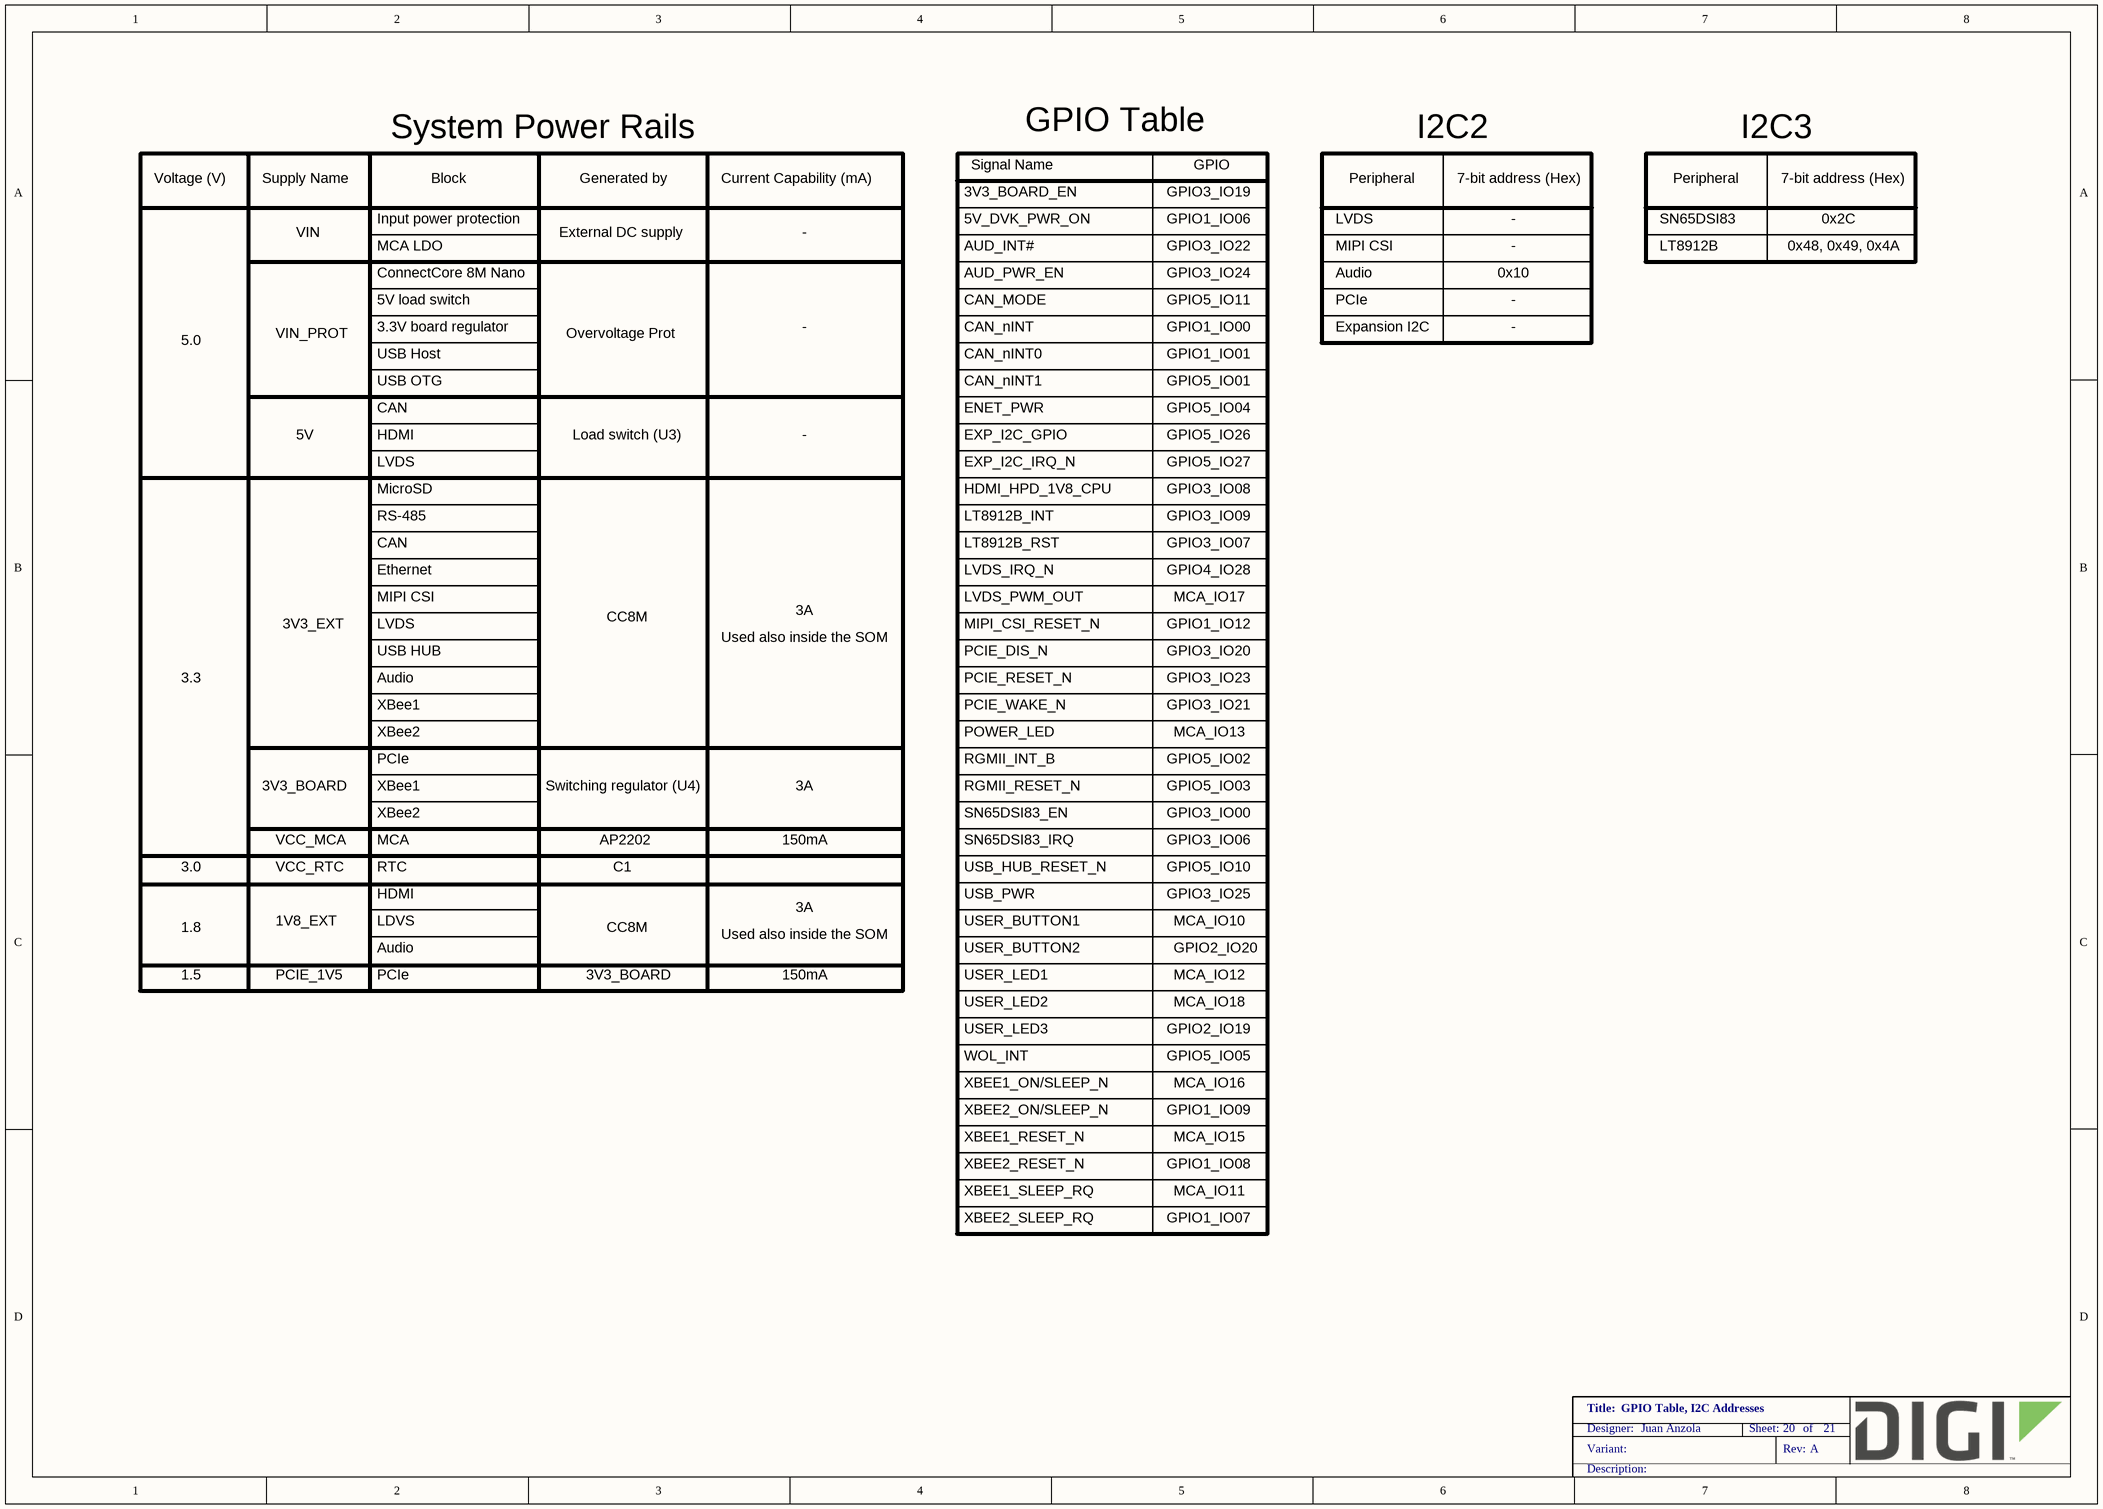
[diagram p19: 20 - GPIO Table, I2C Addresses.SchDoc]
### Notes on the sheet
- Voltage (V)
- Supply Name
- System Power Rails
- Block
- Generated by
- Current Capability (mA)
- Signal Name
- GPIO Table
- GPIO
- Peripheral
- I2C2
- 7-bit address (Hex)
- I2C3
- VIN
- Input power protection
- External DC supply
- -
- 3V3_BOARD_EN
- 5V_DVK_PWR_ON
- GPIO3_IO19
- GPIO1_IO06
- LVDS
- SN65DSI83
- 0x2C
- MCA LDO
- ConnectCore 8M Nano
- 5V load switch
- AUD_INT#
- AUD_PWR_EN
- CAN_MODE
- GPIO3_IO24
- GPIO3_IO22
- GPIO5_IO11
- PCIe
- MIPI CSI
- Audio
- 0x10
- LT8912B
- 0x48, 0x49, 0x4A
- 5.0
- VIN_PROT
- USB Host
- 3.3V board regulator
- Overvoltage Prot
- CAN_nINT
- CAN_nINT0
- GPIO1_IO00
- GPIO1_IO01
- Expansion I2C
- 5V
- HDMI
- USB OTG
- CAN
- Load switch (U3)
- CAN_nINT1
- ENET_PWR
- EXP_I2C_GPIO
- GPIO5_IO01
- GPIO5_IO04
- GPIO5_IO26
- MicroSD
- HDMI_HPD_1V8_CPU
- EXP_I2C_IRQ_N
- GPIO3_IO08
- GPIO5_IO27
- Ethernet
- RS-485
- LT8912B_RST
- LT8912B_INT
- LVDS_IRQ_N
- GPIO3_IO07
- GPIO3_IO09
- GPIO4_IO28
- 3V3_EXT
- CC8M
- Used also inside the SOM
- 3A
- LVDS_PWM_OUT
- MIPI_CSI_RESET_N
- GPIO1_IO12
- MCA_IO17
- 3.3
- USB HUB
- XBee1
- PCIE_WAKE_N
- PCIE_DIS_N
- PCIE_RESET_N
- GPIO3_IO23
- GPIO3_IO21
- GPIO3_IO20
- XBee2
- RGMII_INT_B
- POWER_LED
- GPIO5_IO02
- MCA_IO13
- 3V3_BOARD
- VCC_MCA
- MCA
- Switching regulator (U4)
- AP2202
- 150mA
- SN65DSI83_EN
- SN65DSI83_IRQ
- RGMII_RESET_N
- GPIO3_IO00
- GPIO3_IO06
- GPIO5_IO03
- 3.0
- VCC_RTC
- RTC
- C1
- USB_PWR
- USB_HUB_RESET_N
- GPIO3_IO25
- GPIO5_IO10
- 1.8
- 1.5
- 1V8_EXT
- PCIE_1V5
- LDVS
- USER_LED1
- USER_BUTTON1
- USER_BUTTON2
- MCA_IO12
- MCA_IO10
- GPIO2_IO20
- USER_LED2
- USER_LED3
- GPIO2_IO19
- MCA_IO18
- XBEE2_ON/SLEEP_N
- WOL_INT
- XBEE1_ON/SLEEP_N
- GPIO1_IO09
- GPIO5_IO05
- MCA_IO16
- XBEE2_RESET_N
- XBEE1_RESET_N
- GPIO1_IO08
- MCA_IO15
- XBEE2_SLEEP_RQ
- XBEE1_SLEEP_RQ
- GPIO1_IO07
- MCA_IO11

## Sheet 21 - History, Mechanicals.SchDoc: History, Mechanicals
size A3; PageSetup: Record=PageOptions¦CenterHorizontal=True¦CenterVertical=True¦PrintScale=1.01¦XCorrection=1.00¦YCorrection=1.00¦PrintKind=0¦BorderSize=5000000¦LeftOffset=0¦BottomOffset=0¦Orientation=2¦PaperLength=4200¦PaperWidth=2970¦Scale=100¦PaperSource=15¦PrintQuality=600¦MediaType=1¦DitherType=10¦PrintScaleMode=1¦PaperKind=A3¦PaperIndex=8; Author: Juan Anzola; SheetNumber: 21; SheetTotal: 21

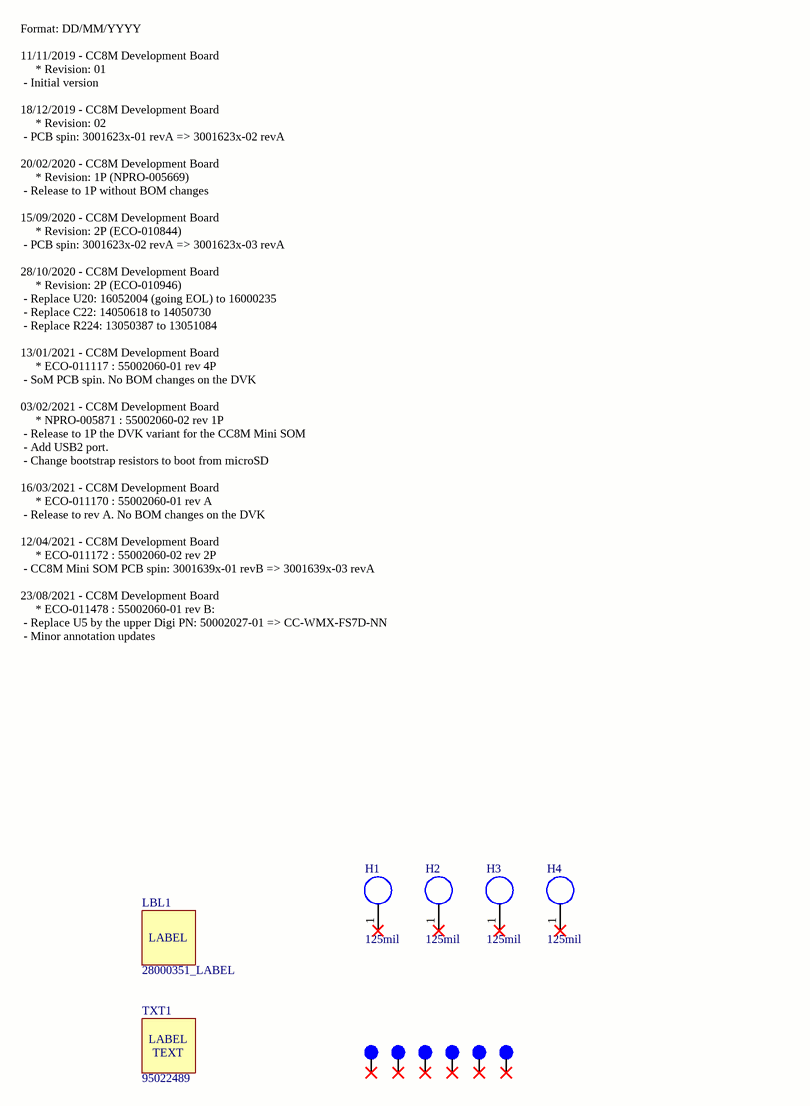
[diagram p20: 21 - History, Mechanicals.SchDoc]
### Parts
FIDUCIAL1  40mil FID  [fiducial_40mil_round]  (value not drawn)  (no BOM)
FIDUCIAL2  40mil FID  [fiducial_40mil_round]  (value not drawn)  (no BOM)
FIDUCIAL3  40mil FID  [fiducial_40mil_round]  (value not drawn)  (no BOM)
FIDUCIAL4  40mil FID  [fiducial_40mil_round]  (value not drawn)  (no BOM)
FIDUCIAL5  40mil FID  [fiducial_40mil_round]  (value not drawn)  (no BOM)
FIDUCIAL6  40mil FID  [fiducial_40mil_round]  (value not drawn)  (no BOM)
H1  125mil  [MH_185_125_NP]  (no BOM)
H2  125mil  [MH_185_125_NP]  (no BOM)
H3  125mil  [MH_185_125_NP]  (no BOM)
H4  125mil  [MH_185_125_NP]  (no BOM)
LBL1  28000351_LABEL
TXT1  95022489  (mechanical)

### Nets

Not connected (* = marked no-connect by the designer): FIDUCIAL1 1(Fid_1)*; FIDUCIAL2 1(Fid_1)*; FIDUCIAL3 1(Fid_1)*; FIDUCIAL4 1(Fid_1)*; FIDUCIAL5 1(Fid_1)*; FIDUCIAL6 1(Fid_1)*; H1 1(TOOL)*; H2 1(TOOL)*; H3 1(TOOL)*; H4 1(TOOL)*

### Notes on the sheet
- Format: DD/MM/YYYY
  11/11/2019 - CC8M Development Board
  * Revision: 01
  - Initial version
  18/12/2019 - CC8M Development Board
  * Revision: 02
  - PCB spin: 3001623x-01 revA => 3001623x-02 revA
  20/02/2020 - CC8M Development Board
  * Revision: 1P (NPRO-005669)
  - Release to 1P without BOM changes
  15/09/2020 - CC8M Development Board
  * Revision: 2P (ECO-010844)
  - PCB spin: 3001623x-02 revA => 3001623x-03 revA
  28/10/2020 - CC8M Development Board
  * Revision: 2P (ECO-010946)
  - Replace U20: 16052004 (going EOL) to 16000235
  - Replace C22: 14050618 to 14050730
  - Replace R224: 13050387 to 13051084
  13/01/2021 - CC8M Development Board
  * ECO-011117 : 55002060-01 rev 4P
  - SoM PCB spin. No BOM changes on the DVK
  03/02/2021 - CC8M Development Board
  * NPRO-005871 : 55002060-02 rev 1P
  - Release to 1P the DVK variant for the CC8M Mini SOM
  - Add USB2 port.
  - Change bootstrap resistors to boot from microSD
  16/03/2021 - CC8M Development Board
  * ECO-011170 : 55002060-01 rev A
  - Release to rev A. No BOM changes on the DVK
  12/04/2021 - CC8M Development Board
  * ECO-011172 : 55002060-02 rev 2P
  - CC8M Mini SOM PCB spin: 3001639x-01 revB => 3001639x-03 revA
  23/08/2021 - CC8M Development Board
  * ECO-011478 : 55002060-01 rev B:
  - Replace U5 by the upper Digi PN: 50002027-01 => CC-WMX-FS7D-NN
  - Minor annotation updates

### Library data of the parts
FIDUCIAL1-FIDUCIAL6 = CAD0023: 40 Mil Round Fiducial; Part_Type: Mechanical; Component_Life_Cycle_State: Reviewed; Area: 1; Project: SDR Prototype RF Board
H1-H4 = CAD0006: NPTH for Tooling, 0.125in dia.; Part_Type: Mechanical; Component_Life_Cycle_State: Proven; Area: 0.98; Project: Adjustable Foundation
LBL1 = 1002170: LBL,Poly White Blank 0.40x0.40; Manufacturer: 3M; Manufacturer_Part_Number: TAAE-014000; Noplace: False; Component_Life_Cycle_State: Created; Area: 100; Project: CCWMX6_SBC board
TXT1 = CAD0102: Text,.5x.75" 55002060-01 IMX8MN (DVK); Part_Type: Label; Noplace: False; Note: CAD ONLY; Component_Life_Cycle_State: Pending; Area: 0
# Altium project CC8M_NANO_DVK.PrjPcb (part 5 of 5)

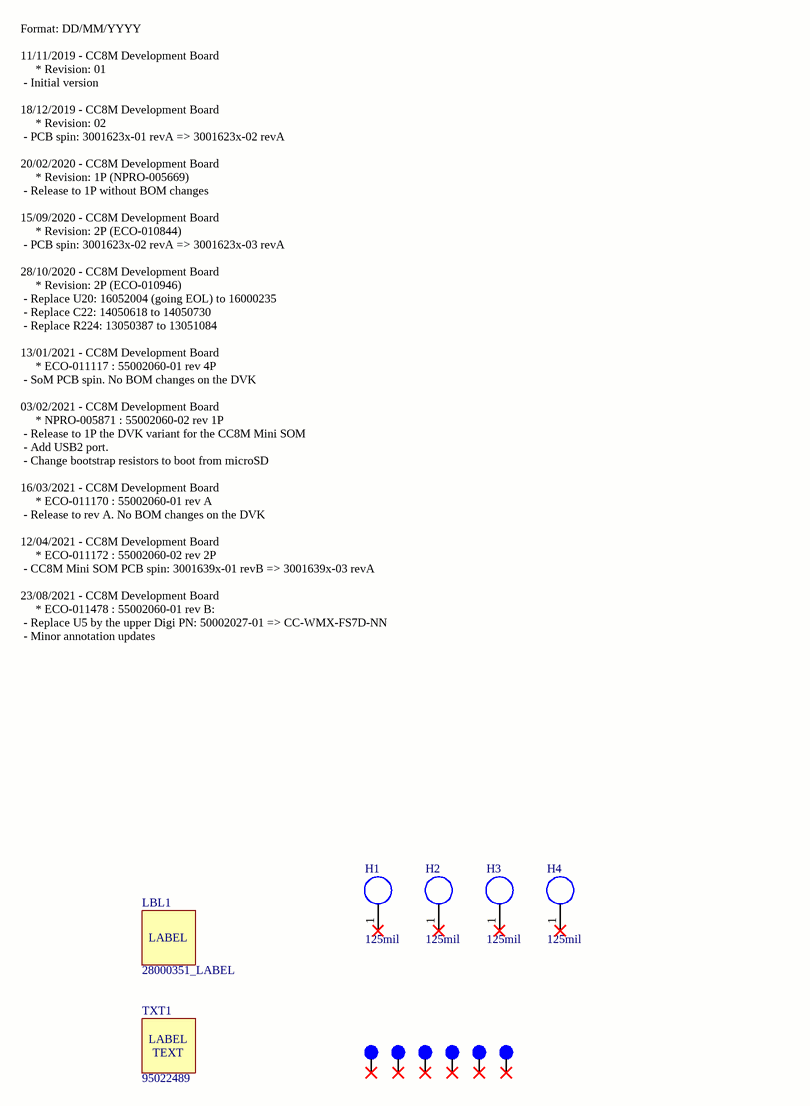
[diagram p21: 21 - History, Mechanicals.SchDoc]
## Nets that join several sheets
1V8: 04 - CCIMX8M Nano Power, Control, MCA (9 pins), 07 - Bootstrap (R77.2 R79.2 R81.1 R83.1)
1V8_SOM_EXT: 04 - CCIMX8M Nano Power, Control, MCA (J8.1 R32.2), 09 - JTAG, SWD, uSD, Mini PCIe, uSIM (J20.1 R164.1), 11 - Ethernet (C60.2 R173.1 R183.2 U14.3), 13 - MIPI to HDMI bridge (31 pins), 14 - MIPI to LVDS bridge (27 pins), 17 - Audio (R282.1 R283.1 R285.1 U16.S), 18 - I2C, XBee (6 pins), 19 - Expansion connectors, User LEDs, RF signals (J52.7)
3V3: 04 - CCIMX8M Nano Power, Control, MCA (12 pins), 07 - Bootstrap (26 pins)
3V3_BOARD: 03 - Power, reset (7 pins), 06 - CCIMX8M Nano RF, PCIe (5 pins), 09 - JTAG, SWD, uSD, Mini PCIe, uSIM (17 pins), 18 - I2C, XBee (L39.1 L41.1 R306.2 R311.2), 19 - Expansion connectors, User LEDs, RF signals (J52.5)
3V3_RF: 04 - CCIMX8M Nano Power, Control, MCA (U5.F17 U5.F18), 06 - CCIMX8M Nano RF, PCIe (J12.2 R42.2 R46.2 R53.2), 19 - Expansion connectors, User LEDs, RF signals (J49.1 J52.6)
3V3_SOM_EXT: 03 - Power, reset (R10.2 R25.2), 04 - CCIMX8M Nano Power, Control, MCA (J7.1 R31.2), 07 - Bootstrap (S1.5), 08 - Consoles (R133.1), 09 - JTAG, SWD, uSD, Mini PCIe, uSIM (R156.2), 10 - RS485, CAN (7 pins), 11 - Ethernet (R170.1 R171.1 R174.1 U13.S), 12 - MIPI display and switch, MIPI camera (7 pins), 13 - MIPI to HDMI bridge (D8.A), 14 - MIPI to LVDS bridge (J32.1 R244.1), 15 - USB HUB (R257.1 R258.1 R260.1 U26.S), 16 - USB Recovery, USB OTG (5 pins), 17 - Audio (5 pins), 18 - I2C, XBee (L38.1 L40.1 R34.2 R362.2), 19 - Expansion connectors, User LEDs, RF signals (6 pins)
5V: 03 - Power, reset (R19.2), 08 - Consoles (R132.1), 10 - RS485, CAN (C56.1 J24.1 U11.3), 13 - MIPI to HDMI bridge (C82.2 C83.2 U20.1), 14 - MIPI to LVDS bridge (L17.1), 19 - Expansion connectors, User LEDs, RF signals (J52.3)
GND: 03 - Power, reset (47 pins), 04 - CCIMX8M Nano Power, Control, MCA (178 pins), 06 - CCIMX8M Nano RF, PCIe (33 pins), 07 - Bootstrap (30 pins), 08 - Consoles (28 pins), 09 - JTAG, SWD, uSD, Mini PCIe, uSIM (63 pins), 10 - RS485, CAN (17 pins), 11 - Ethernet (40 pins), 12 - MIPI display and switch, MIPI camera (16 pins), 13 - MIPI to HDMI bridge (56 pins), 14 - MIPI to LVDS bridge (27 pins), 15 - USB HUB (35 pins), 16 - USB Recovery, USB OTG (25 pins), 17 - Audio (33 pins), 18 - I2C, XBee (12 pins), 19 - Expansion connectors, User LEDs, RF signals (28 pins)
MUX_3V3_1V8: 04 - CCIMX8M Nano Power, Control, MCA (R35.1 R343.1), 09 - JTAG, SWD, uSD, Mini PCIe, uSIM (R155.2)
SHLD: 11 - Ethernet (J27.SHLD1 J27.SHLD2 R180.2), 13 - MIPI to HDMI bridge (J31.M1 J31.M2 J31.M3 J31.M4), 15 - USB HUB (J33.SH1 J33.SH2 J33.SH3 J33.SH4), 16 - USB Recovery, USB OTG (J34.6 J34.7 J34.8 J34.9)
VCC_MCA: 03 - Power, reset (7 pins), 04 - CCIMX8M Nano Power, Control, MCA (J9.1 R341.2 R348.2 U5.AM21), 09 - JTAG, SWD, uSD, Mini PCIe, uSIM (J22.1 SWD.1 SWD.5), 19 - Expansion connectors, User LEDs, RF signals (5 pins)
VDDA_1V8: 04 - CCIMX8M Nano Power, Control, MCA (U5.AH18), 19 - Expansion connectors, User LEDs, RF signals (J52.8)
VIN: 03 - Power, reset (10 pins), 16 - USB Recovery, USB OTG (J36.1)
VIN_PROT: 03 - Power, reset (15 pins), 04 - CCIMX8M Nano Power, Control, MCA (J6.1 R28.1), 15 - USB HUB (C126.1 U23.7), 16 - USB Recovery, USB OTG (C141.2 C194.2 U27.7 U36.7), 18 - I2C, XBee (R305.1 R310.1)
VSYS: 04 - CCIMX8M Nano Power, Control, MCA (R29.2 U5.AL6 U5.AL7 U5.AL8), 16 - USB Recovery, USB OTG (R354.2)
VSYS2: 03 - Power, reset (J5.1), 04 - CCIMX8M Nano Power, Control, MCA (7 pins)
3V3_BOARD_EN: 03 - Power, reset (R22.1), 05 - CCIMX8M Nano Digital interfaces (U5.E25)
5V_DVK_PWR_ON: 03 - Power, reset (R25.1 U3.4), 05 - CCIMX8M Nano Digital interfaces (U5.E26)
AUD_I2C_SCL: 17 - Audio (U29.51), 18 - I2C, XBee (R296.2)
AUD_I2C_SDA: 17 - Audio (U29.52), 18 - I2C, XBee (R298.2)
AUD_INT#: 05 - CCIMX8M Nano Digital interfaces (U5.AG8), 17 - Audio (R268.2 U29.56)
AUD_PWR_EN: 05 - CCIMX8M Nano Digital interfaces (U5.E27), 17 - Audio (Q7.G Q9.G R281.2 R285.2)
BT_UART1_CTS#: 06 - CCIMX8M Nano RF, PCIe (R58.2), 19 - Expansion connectors, User LEDs, RF signals (J49.9)
BT_UART1_RTS#: 06 - CCIMX8M Nano RF, PCIe (R59.2), 19 - Expansion connectors, User LEDs, RF signals (J49.7)
BT_UART1_RX: 06 - CCIMX8M Nano RF, PCIe (R57.2), 19 - Expansion connectors, User LEDs, RF signals (J49.5)
BT_UART1_TX: 06 - CCIMX8M Nano RF, PCIe (R56.2), 19 - Expansion connectors, User LEDs, RF signals (J49.3)
BT_WAKEUP_HOST: 06 - CCIMX8M Nano RF, PCIe (U5.G17), 19 - Expansion connectors, User LEDs, RF signals (J44.1)
BT_WAKEUP_SLAVE: 06 - CCIMX8M Nano RF, PCIe (U5.G12), 19 - Expansion connectors, User LEDs, RF signals (J44.3)
CAN_MODE: 05 - CCIMX8M Nano Digital interfaces (U5.E18), 10 - RS485, CAN (R167.1)
CAN_nINT: 05 - CCIMX8M Nano Digital interfaces (U5.AA1), 10 - RS485, CAN (U10.4)
CAN_nINT0: 05 - CCIMX8M Nano Digital interfaces (U5.AN4), 10 - RS485, CAN (U10.9)
CAN_nINT1: 05 - CCIMX8M Nano Digital interfaces (U5.F29), 10 - RS485, CAN (U10.8)
CLKIN1: 04 - CCIMX8M Nano Power, Control, MCA (U5.AM10), 19 - Expansion connectors, User LEDs, RF signals (J50.1)
CLKIN2: 04 - CCIMX8M Nano Power, Control, MCA (U5.AM11), 19 - Expansion connectors, User LEDs, RF signals (J50.3)
CLKOUT1: 04 - CCIMX8M Nano Power, Control, MCA (U5.AM7), 19 - Expansion connectors, User LEDs, RF signals (J50.5)
CLKOUT2: 04 - CCIMX8M Nano Power, Control, MCA (U5.AM9), 19 - Expansion connectors, User LEDs, RF signals (J50.7)
CONSOLE_RX: 05 - CCIMX8M Nano Digital interfaces (U5.V29), 08 - Consoles (J17.3 R141.2)
CONSOLE_TX: 05 - CCIMX8M Nano Digital interfaces (U5.W29), 08 - Consoles (J17.2 R142.2)
ENET_PWR: 05 - CCIMX8M Nano Digital interfaces (U5.AF1), 11 - Ethernet (Q2.G R174.2)
EXP_I2C_GPIO: 05 - CCIMX8M Nano Digital interfaces (U5.AG26), 19 - Expansion connectors, User LEDs, RF signals (J48.7)
EXP_I2C_IRQ_N: 05 - CCIMX8M Nano Digital interfaces (U5.AG27), 19 - Expansion connectors, User LEDs, RF signals (J48.5)
EXP_I2C_SCL: 05 - CCIMX8M Nano Digital interfaces (U5.V1), 19 - Expansion connectors, User LEDs, RF signals (J48.1)
EXP_I2C_SDA: 05 - CCIMX8M Nano Digital interfaces (U5.W1), 19 - Expansion connectors, User LEDs, RF signals (J48.3)
GPIO1_IO03: 05 - CCIMX8M Nano Digital interfaces (U5.AG14), 19 - Expansion connectors, User LEDs, RF signals (J46.2)
GPIO1_IO10: 05 - CCIMX8M Nano Digital interfaces (U5.AG13), 19 - Expansion connectors, User LEDs, RF signals (J46.3)
GPIO1_IO11: 05 - CCIMX8M Nano Digital interfaces (U5.AG10), 19 - Expansion connectors, User LEDs, RF signals (J46.5)
GPIO1_IO13: 05 - CCIMX8M Nano Digital interfaces (U5.C9), 16 - USB Recovery, USB OTG (R351.1 U36.2), 19 - Expansion connectors, User LEDs, RF signals (J46.7)
GPIO1_IO14: 05 - CCIMX8M Nano Digital interfaces (U5.C7), 16 - USB Recovery, USB OTG (R184.2 U27.1), 19 - Expansion connectors, User LEDs, RF signals (J46.9)
GPIO1_IO15: 05 - CCIMX8M Nano Digital interfaces (U5.C11), 16 - USB Recovery, USB OTG (R261.1 U27.2), 19 - Expansion connectors, User LEDs, RF signals (J46.4)
GPIO3_IO01_1V8: 05 - CCIMX8M Nano Digital interfaces (U5.K29), 19 - Expansion connectors, User LEDs, RF signals (J46.6)
GPIO3_IO14_1V8: 05 - CCIMX8M Nano Digital interfaces (U5.AG25), 19 - Expansion connectors, User LEDs, RF signals (J46.8)
HDMI_HPD_1V8_CPU: 05 - CCIMX8M Nano Digital interfaces (U5.AG15), 13 - MIPI to HDMI bridge (R232.2)
HDMI_SCL_1V8: 13 - MIPI to HDMI bridge (R327.1 R328.1 U20.17), 18 - I2C, XBee (R286.2)
HDMI_SDA_1V8: 13 - MIPI to HDMI bridge (R329.1 R330.1 U20.18), 18 - I2C, XBee (R287.2)
I2C2_SCL_1V8: 05 - CCIMX8M Nano Digital interfaces (U5.F28), 13 - MIPI to HDMI bridge (R328.2), 18 - I2C, XBee (R33.1 R340.1 U35.1)
I2C2_SCL_3V3: 18 - I2C, XBee (6 pins), 19 - Expansion connectors, User LEDs, RF signals (J48.2)
I2C2_SDA_1V8: 05 - CCIMX8M Nano Digital interfaces (U5.E29), 13 - MIPI to HDMI bridge (R330.2), 18 - I2C, XBee (R361.1 R363.1 U35.4)
I2C2_SDA_3V3: 18 - I2C, XBee (6 pins), 19 - Expansion connectors, User LEDs, RF signals (J48.4)
I2C3_SCL_1V8: 05 - CCIMX8M Nano Digital interfaces (U5.AK25), 18 - I2C, XBee (5 pins), 19 - Expansion connectors, User LEDs, RF signals (J48.6)
I2C3_SDA_1V8: 05 - CCIMX8M Nano Digital interfaces (U5.AK24), 18 - I2C, XBee (5 pins), 19 - Expansion connectors, User LEDs, RF signals (J48.8)
IMX8_ON_OFF: 03 - Power, reset (R4.2), 04 - CCIMX8M Nano Power, Control, MCA (U5.AG18)
JTAG_TCK: 04 - CCIMX8M Nano Power, Control, MCA (U5.AG20), 09 - JTAG, SWD, uSD, Mini PCIe, uSIM (J20.4)
JTAG_TDI: 04 - CCIMX8M Nano Power, Control, MCA (U5.AH27), 09 - JTAG, SWD, uSD, Mini PCIe, uSIM (J20.8)
JTAG_TDO: 04 - CCIMX8M Nano Power, Control, MCA (U5.AG21), 09 - JTAG, SWD, uSD, Mini PCIe, uSIM (J20.6)
JTAG_TMS: 04 - CCIMX8M Nano Power, Control, MCA (U5.AH28), 09 - JTAG, SWD, uSD, Mini PCIe, uSIM (J20.2)
JTAG_TRST_GPIO: 04 - CCIMX8M Nano Power, Control, MCA (U5.AG19), 09 - JTAG, SWD, uSD, Mini PCIe, uSIM (R164.2)
LINE1_IN_L: 17 - Audio (L35.1), 19 - Expansion connectors, User LEDs, RF signals (J53.2)
LINE1_IN_R: 17 - Audio (L34.1), 19 - Expansion connectors, User LEDs, RF signals (J53.1)
LINE2_IN_L: 17 - Audio (L37.1), 19 - Expansion connectors, User LEDs, RF signals (J53.4)
LINE2_IN_R: 17 - Audio (L36.1), 19 - Expansion connectors, User LEDs, RF signals (J53.3)
LINE_OUT_L: 17 - Audio (U29.24), 19 - Expansion connectors, User LEDs, RF signals (J53.6)
LINE_OUT_R: 17 - Audio (U29.23), 19 - Expansion connectors, User LEDs, RF signals (J53.5)
LT8912B_CLK_N: 12 - MIPI display and switch, MIPI camera (U17.16), 13 - MIPI to HDMI bridge (U19.8)
LT8912B_CLK_P: 12 - MIPI display and switch, MIPI camera (U17.17), 13 - MIPI to HDMI bridge (U19.7)
LT8912B_D0_N: 12 - MIPI display and switch, MIPI camera (U18.14), 13 - MIPI to HDMI bridge (U19.2)
LT8912B_D0_P: 12 - MIPI display and switch, MIPI camera (U18.15), 13 - MIPI to HDMI bridge (U19.1)
LT8912B_D1_N: 12 - MIPI display and switch, MIPI camera (U18.12), 13 - MIPI to HDMI bridge (U19.4)
LT8912B_D1_P: 12 - MIPI display and switch, MIPI camera (U18.13), 13 - MIPI to HDMI bridge (U19.3)
LT8912B_D2_N: 12 - MIPI display and switch, MIPI camera (U17.14), 13 - MIPI to HDMI bridge (U19.10)
LT8912B_D2_P: 12 - MIPI display and switch, MIPI camera (U17.15), 13 - MIPI to HDMI bridge (U19.9)
LT8912B_D3_N: 12 - MIPI display and switch, MIPI camera (U17.12), 13 - MIPI to HDMI bridge (U19.12)
LT8912B_D3_P: 12 - MIPI display and switch, MIPI camera (U17.13), 13 - MIPI to HDMI bridge (U19.11)
LT8912B_INT: 05 - CCIMX8M Nano Digital interfaces (U5.D25), 13 - MIPI to HDMI bridge (U19.63)
LT8912B_RST: 05 - CCIMX8M Nano Digital interfaces (U5.A12), 13 - MIPI to HDMI bridge (R225.2 U19.64)
LT8912B_SCL: 13 - MIPI to HDMI bridge (U19.62), 18 - I2C, XBee (R301.2)
LT8912B_SDA: 13 - MIPI to HDMI bridge (U19.61), 18 - I2C, XBee (R303.2)
LTE_ACTIVE: 06 - CCIMX8M Nano RF, PCIe (U5.G15), 19 - Expansion connectors, User LEDs, RF signals (J44.6)
LTE_PRI: 06 - CCIMX8M Nano RF, PCIe (U5.E10), 19 - Expansion connectors, User LEDs, RF signals (J44.2)
LTE_SYNC: 06 - CCIMX8M Nano RF, PCIe (U5.E11), 19 - Expansion connectors, User LEDs, RF signals (J44.4)
LVDS_I2C_SCL: 14 - MIPI to LVDS bridge (J32.17), 18 - I2C, XBee (R288.2)
LVDS_I2C_SDA: 14 - MIPI to LVDS bridge (J32.18), 18 - I2C, XBee (R289.2)
LVDS_IRQ_N: 05 - CCIMX8M Nano Digital interfaces (U5.E28), 14 - MIPI to LVDS bridge (J32.19 R244.2)
LVDS_PWM_OUT: 04 - CCIMX8M Nano Power, Control, MCA (U5.AL23), 14 - MIPI to LVDS bridge (J32.16)
MCA_CLKOUT32K: 04 - CCIMX8M Nano Power, Control, MCA (U5.AL21), 19 - Expansion connectors, User LEDs, RF signals (J43.4)
MCA_VIN_DET: 03 - Power, reset (R339.2 U32.1), 04 - CCIMX8M Nano Power, Control, MCA (U5.AM27)
MCA_VREF_OUT: 04 - CCIMX8M Nano Power, Control, MCA (U5.AM24), 19 - Expansion connectors, User LEDs, RF signals (J43.6)
MIPI_CSI_CLK_N: 05 - CCIMX8M Nano Digital interfaces (U5.AM14), 12 - MIPI display and switch, MIPI camera (J29.8)
MIPI_CSI_CLK_P: 05 - CCIMX8M Nano Digital interfaces (U5.AM13), 12 - MIPI display and switch, MIPI camera (J29.7)
MIPI_CSI_DATA0_N: 05 - CCIMX8M Nano Digital interfaces (U5.AL16), 12 - MIPI display and switch, MIPI camera (J29.14)
MIPI_CSI_DATA0_P: 05 - CCIMX8M Nano Digital interfaces (U5.AL15), 12 - MIPI display and switch, MIPI camera (J29.13)
MIPI_CSI_DATA1_N: 05 - CCIMX8M Nano Digital interfaces (U5.AL13), 12 - MIPI display and switch, MIPI camera (J29.11)
MIPI_CSI_DATA1_P: 05 - CCIMX8M Nano Digital interfaces (U5.AL12), 12 - MIPI display and switch, MIPI camera (J29.10)
MIPI_CSI_DATA2_N: 05 - CCIMX8M Nano Digital interfaces (U5.AM17), 19 - Expansion connectors, User LEDs, RF signals (J28.5)
MIPI_CSI_DATA2_P: 05 - CCIMX8M Nano Digital interfaces (U5.AM16), 19 - Expansion connectors, User LEDs, RF signals (J28.4)
MIPI_CSI_DATA3_N: 05 - CCIMX8M Nano Digital interfaces (U5.AK22), 19 - Expansion connectors, User LEDs, RF signals (J28.2)
MIPI_CSI_DATA3_P: 05 - CCIMX8M Nano Digital interfaces (U5.AK21), 19 - Expansion connectors, User LEDs, RF signals (J28.1)
MIPI_CSI_I2C_SCL: 12 - MIPI display and switch, MIPI camera (J29.3), 18 - I2C, XBee (R290.2)
MIPI_CSI_I2C_SDA: 12 - MIPI display and switch, MIPI camera (J29.2), 18 - I2C, XBee (R293.2)
MIPI_CSI_RESET_N: 05 - CCIMX8M Nano Digital interfaces (R352.1), 12 - MIPI display and switch, MIPI camera (J29.5)
MIPI_DSI_CLK_N: 05 - CCIMX8M Nano Digital interfaces (U5.AN6), 12 - MIPI display and switch, MIPI camera (R206.1 R207.1)
MIPI_DSI_CLK_P: 05 - CCIMX8M Nano Digital interfaces (U5.AN7), 12 - MIPI display and switch, MIPI camera (R204.1 R205.1)
MIPI_DSI_DATA0_N: 05 - CCIMX8M Nano Digital interfaces (U5.AN9), 12 - MIPI display and switch, MIPI camera (R210.1 R211.1)
MIPI_DSI_DATA0_P: 05 - CCIMX8M Nano Digital interfaces (U5.AN10), 12 - MIPI display and switch, MIPI camera (R208.1 R209.1)
MIPI_DSI_DATA1_N: 05 - CCIMX8M Nano Digital interfaces (U5.AN12), 12 - MIPI display and switch, MIPI camera (R214.1 R215.1)
MIPI_DSI_DATA1_P: 05 - CCIMX8M Nano Digital interfaces (U5.AN13), 12 - MIPI display and switch, MIPI camera (R212.1 R213.1)
MIPI_DSI_DATA2_N: 05 - CCIMX8M Nano Digital interfaces (U5.AN15), 12 - MIPI display and switch, MIPI camera (R218.1 R219.1)
MIPI_DSI_DATA2_P: 05 - CCIMX8M Nano Digital interfaces (U5.AN16), 12 - MIPI display and switch, MIPI camera (R216.1 R217.1)
MIPI_DSI_DATA3_N: 05 - CCIMX8M Nano Digital interfaces (U5.AN18), 12 - MIPI display and switch, MIPI camera (R222.1 R223.1)
MIPI_DSI_DATA3_P: 05 - CCIMX8M Nano Digital interfaces (U5.AN19), 12 - MIPI display and switch, MIPI camera (R220.1 R221.1)
MIPI_SWITCH_SEL: 07 - Bootstrap (S1.4), 12 - MIPI display and switch, MIPI camera (R337.1 R338.2 U17.11 U18.11)
MUX_VSELECT: 04 - CCIMX8M Nano Power, Control, MCA (U5.AH13), 05 - CCIMX8M Nano Digital interfaces (U5.AN5)
PCIE_CLK_N: 06 - CCIMX8M Nano RF, PCIe (R72.2 R74.2), 09 - JTAG, SWD, uSD, Mini PCIe, uSIM (C45.1)
PCIE_CLK_P: 06 - CCIMX8M Nano RF, PCIe (R71.2 R73.2), 09 - JTAG, SWD, uSD, Mini PCIe, uSIM (C46.1)
PCIE_DIS_N: 05 - CCIMX8M Nano Digital interfaces (U5.E24), 09 - JTAG, SWD, uSD, Mini PCIe, uSIM (J19.20)
PCIE_I2C_SCL: 09 - JTAG, SWD, uSD, Mini PCIe, uSIM (J19.30), 18 - I2C, XBee (R300.2)
PCIE_I2C_SDA: 09 - JTAG, SWD, uSD, Mini PCIe, uSIM (J19.32), 18 - I2C, XBee (R302.2)
PCIE_RESET_N: 05 - CCIMX8M Nano Digital interfaces (U5.E3), 09 - JTAG, SWD, uSD, Mini PCIe, uSIM (J19.22)
PCIE_RX_N: 06 - CCIMX8M Nano RF, PCIe (R68.1), 09 - JTAG, SWD, uSD, Mini PCIe, uSIM (J19.23)
PCIE_RX_P: 06 - CCIMX8M Nano RF, PCIe (R67.1), 09 - JTAG, SWD, uSD, Mini PCIe, uSIM (J19.25)
PCIE_TX_N: 06 - CCIMX8M Nano RF, PCIe (C25.2), 09 - JTAG, SWD, uSD, Mini PCIe, uSIM (J19.31)
PCIE_TX_P: 06 - CCIMX8M Nano RF, PCIe (C24.2), 09 - JTAG, SWD, uSD, Mini PCIe, uSIM (J19.33)
PCIE_WAKE_N: 05 - CCIMX8M Nano Digital interfaces (U5.D19), 09 - JTAG, SWD, uSD, Mini PCIe, uSIM (J19.1 R160.1)
PCM_CLK: 06 - CCIMX8M Nano RF, PCIe (U5.G13), 17 - Audio (R269.1), 19 - Expansion connectors, User LEDs, RF signals (J44.5)
PCM_IN: 06 - CCIMX8M Nano RF, PCIe (U5.G14), 17 - Audio (R272.1), 19 - Expansion connectors, User LEDs, RF signals (J44.7)
PCM_OUT: 06 - CCIMX8M Nano RF, PCIe (U5.F13), 17 - Audio (R271.1), 19 - Expansion connectors, User LEDs, RF signals (J44.9)
PCM_SYNC: 06 - CCIMX8M Nano RF, PCIe (U5.F14), 17 - Audio (R270.1)
POR_B: 03 - Power, reset (R6.2), 04 - CCIMX8M Nano Power, Control, MCA (U5.AH10), 09 - JTAG, SWD, uSD, Mini PCIe, uSIM (J20.10)
POWER_BUTTON: 03 - Power, reset (R2.1 R4.1 SW1.3 SW1.4), 19 - Expansion connectors, User LEDs, RF signals (J43.2)
POWER_LED: 03 - Power, reset (Q1.G R11.1), 04 - CCIMX8M Nano Power, Control, MCA (U5.AL22)
PWR_ON: 03 - Power, reset (R8.1), 04 - CCIMX8M Nano Power, Control, MCA (U5.AJ12)
RESERVED: 06 - CCIMX8M Nano RF, PCIe (U5.F19), 19 - Expansion connectors, User LEDs, RF signals (J44.8)
RGMII_INT_ B: 05 - CCIMX8M Nano Digital interfaces (U5.G29), 11 - Ethernet (R183.1 U15.5)
RGMII_MDC: 05 - CCIMX8M Nano Digital interfaces (U5.A10), 11 - Ethernet (U14.5)
RGMII_MDIO: 05 - CCIMX8M Nano Digital interfaces (U5.A11), 11 - Ethernet (U14.4)
RGMII_RD0: 05 - CCIMX8M Nano Digital interfaces (U5.A16), 11 - Ethernet (R186.1 R195.2 U15.31)
RGMII_RD1: 05 - CCIMX8M Nano Digital interfaces (U5.A15), 11 - Ethernet (R187.1 R196.2 U15.30)
RGMII_RD2: 05 - CCIMX8M Nano Digital interfaces (U5.A14), 11 - Ethernet (R190.1 R199.2 U15.28)
RGMII_RD3: 05 - CCIMX8M Nano Digital interfaces (U5.A13), 11 - Ethernet (R192.1 R201.2 U15.27)
RGMII_RESET_N: 05 - CCIMX8M Nano Digital interfaces (U5.AG1), 11 - Ethernet (R179.1)
RGMII_RX_CTL: 05 - CCIMX8M Nano Digital interfaces (U5.A17), 11 - Ethernet (R189.1 R198.2 U15.32)
RGMII_RXC: 05 - CCIMX8M Nano Digital interfaces (U5.A18), 11 - Ethernet (R191.1 R200.2 U15.33)
RGMII_TD0: 05 - CCIMX8M Nano Digital interfaces (U5.A22), 11 - Ethernet (U15.36)
RGMII_TD1: 05 - CCIMX8M Nano Digital interfaces (U5.A21), 11 - Ethernet (U15.37)
RGMII_TD2: 05 - CCIMX8M Nano Digital interfaces (U5.A20), 11 - Ethernet (U15.38)
RGMII_TD3: 05 - CCIMX8M Nano Digital interfaces (U5.A19), 11 - Ethernet (U15.39)
RGMII_TX_CTL: 05 - CCIMX8M Nano Digital interfaces (U5.A23), 11 - Ethernet (U15.34)
RGMII_TXC: 05 - CCIMX8M Nano Digital interfaces (U5.A24), 11 - Ethernet (U15.35)
RXD_MAX98089: 13 - MIPI to HDMI bridge (R237.2), 17 - Audio (U29.7)
SAI1_MCLK: 05 - CCIMX8M Nano Digital interfaces (U5.AH22), 19 - Expansion connectors, User LEDs, RF signals (J47.23)
SAI1_RXC: 05 - CCIMX8M Nano Digital interfaces (U5.AH20), 19 - Expansion connectors, User LEDs, RF signals (J47.6)
SAI1_RXD0: 05 - CCIMX8M Nano Digital interfaces (U5.AJ22), 07 - Bootstrap (R85.2 R101.1), 19 - Expansion connectors, User LEDs, RF signals (J47.8)
SAI1_RXD1: 05 - CCIMX8M Nano Digital interfaces (U5.P29), 07 - Bootstrap (R86.2 R102.1 U7.2), 19 - Expansion connectors, User LEDs, RF signals (J47.10)
SAI1_RXD2: 05 - CCIMX8M Nano Digital interfaces (U5.R29), 07 - Bootstrap (R87.2 R103.1 U7.4), 19 - Expansion connectors, User LEDs, RF signals (J47.12)
SAI1_RXD3: 05 - CCIMX8M Nano Digital interfaces (U5.B19), 07 - Bootstrap (R88.2 R104.1), 19 - Expansion connectors, User LEDs, RF signals (J47.14)
SAI1_RXD4: 05 - CCIMX8M Nano Digital interfaces (U5.B20), 07 - Bootstrap (R89.2 R105.1 U7.7), 19 - Expansion connectors, User LEDs, RF signals (J47.16)
SAI1_RXD5: 05 - CCIMX8M Nano Digital interfaces (U5.B21), 07 - Bootstrap (R90.2 R106.1), 19 - Expansion connectors, User LEDs, RF signals (J47.18)
SAI1_RXD6: 05 - CCIMX8M Nano Digital interfaces (U5.B22), 07 - Bootstrap (R91.2 R107.1), 19 - Expansion connectors, User LEDs, RF signals (J47.20)
SAI1_RXD7: 05 - CCIMX8M Nano Digital interfaces (U5.C20), 07 - Bootstrap (R92.2 R108.1), 19 - Expansion connectors, User LEDs, RF signals (J47.22)
SAI1_RXFS: 05 - CCIMX8M Nano Digital interfaces (U5.AJ24), 19 - Expansion connectors, User LEDs, RF signals (J47.4)
SAI1_TXC: 05 - CCIMX8M Nano Digital interfaces (U5.AK28), 19 - Expansion connectors, User LEDs, RF signals (J47.5)
SAI1_TXD0: 05 - CCIMX8M Nano Digital interfaces (U5.AJ21), 07 - Bootstrap (R93.2 R109.1), 19 - Expansion connectors, User LEDs, RF signals (J47.7)
SAI1_TXD1: 05 - CCIMX8M Nano Digital interfaces (U5.AK26), 07 - Bootstrap (R94.2 R110.1), 19 - Expansion connectors, User LEDs, RF signals (J47.9)
SAI1_TXD2: 05 - CCIMX8M Nano Digital interfaces (U5.AK27), 07 - Bootstrap (R95.2 R111.1 U7.3), 19 - Expansion connectors, User LEDs, RF signals (J47.11)
SAI1_TXD3: 05 - CCIMX8M Nano Digital interfaces (U5.AH25), 07 - Bootstrap (R96.2 R112.1 U7.5), 19 - Expansion connectors, User LEDs, RF signals (J47.13)
SAI1_TXD4: 05 - CCIMX8M Nano Digital interfaces (U5.AH26), 07 - Bootstrap (R97.2 R113.1 U7.6), 19 - Expansion connectors, User LEDs, RF signals (J47.15)
SAI1_TXD5: 05 - CCIMX8M Nano Digital interfaces (U5.AJ25), 07 - Bootstrap (R98.2 R114.1 U7.8), 19 - Expansion connectors, User LEDs, RF signals (J47.17)
SAI1_TXD6: 05 - CCIMX8M Nano Digital interfaces (U5.AH24), 07 - Bootstrap (R99.2 R115.1), 19 - Expansion connectors, User LEDs, RF signals (J47.19)
SAI1_TXD7: 05 - CCIMX8M Nano Digital interfaces (U5.AJ23), 07 - Bootstrap (R100.2 R116.1), 19 - Expansion connectors, User LEDs, RF signals (J47.21)
SAI1_TXFS: 05 - CCIMX8M Nano Digital interfaces (U5.AH23), 19 - Expansion connectors, User LEDs, RF signals (J47.3)
SAI2_MCLK: 05 - CCIMX8M Nano Digital interfaces (U5.B24), 17 - Audio (U29.5)
SAI2_RXD: 05 - CCIMX8M Nano Digital interfaces (U5.E21), 13 - MIPI to HDMI bridge (R237.1)
SAI2_TXC: 05 - CCIMX8M Nano Digital interfaces (U5.E23), 13 - MIPI to HDMI bridge (R238.1 R239.1)
SAI2_TXD: 05 - CCIMX8M Nano Digital interfaces (U5.E20), 13 - MIPI to HDMI bridge (R235.1 R236.1)
SAI2_TXFS: 05 - CCIMX8M Nano Digital interfaces (U5.C19), 13 - MIPI to HDMI bridge (R240.1 R241.1)
SCU_BOOT_MODE0: 04 - CCIMX8M Nano Power, Control, MCA (U5.AE29), 07 - Bootstrap (R80.2 S1.2 TP7.1)
SCU_BOOT_MODE1: 04 - CCIMX8M Nano Power, Control, MCA (U5.AD29), 07 - Bootstrap (R77.1 S1.1 TP6.1)
SCU_BOOT_MODE2: 04 - CCIMX8M Nano Power, Control, MCA (U5.AJ28), 07 - Bootstrap (R81.2 R82.2)
SCU_BOOT_MODE3: 04 - CCIMX8M Nano Power, Control, MCA (U5.AJ27), 07 - Bootstrap (R83.2 R84.2)
SN65DSI83_CLK_N: 12 - MIPI display and switch, MIPI camera (U17.23), 14 - MIPI to LVDS bridge (U21.25)
SN65DSI83_CLK_P: 12 - MIPI display and switch, MIPI camera (U17.22), 14 - MIPI to LVDS bridge (U21.24)
SN65DSI83_D0_N: 12 - MIPI display and switch, MIPI camera (U18.21), 14 - MIPI to LVDS bridge (U21.20)
SN65DSI83_D0_P: 12 - MIPI display and switch, MIPI camera (U18.20), 14 - MIPI to LVDS bridge (U21.19)
SN65DSI83_D1_N: 12 - MIPI display and switch, MIPI camera (U18.18), 14 - MIPI to LVDS bridge (U21.22)
SN65DSI83_D1_P: 12 - MIPI display and switch, MIPI camera (U18.19), 14 - MIPI to LVDS bridge (U21.21)
SN65DSI83_D2_N: 12 - MIPI display and switch, MIPI camera (U17.21), 14 - MIPI to LVDS bridge (U21.28)
SN65DSI83_D2_P: 12 - MIPI display and switch, MIPI camera (U17.20), 14 - MIPI to LVDS bridge (U21.27)
SN65DSI83_D3_N: 12 - MIPI display and switch, MIPI camera (U17.18), 14 - MIPI to LVDS bridge (U21.30)
SN65DSI83_D3_P: 12 - MIPI display and switch, MIPI camera (U17.19), 14 - MIPI to LVDS bridge (U21.29)
SN65DSI83_EN: 05 - CCIMX8M Nano Digital interfaces (U5.AG28), 14 - MIPI to LVDS bridge (R243.2 U21.2)
SN65DSI83_IRQ: 05 - CCIMX8M Nano Digital interfaces (U5.AL18), 14 - MIPI to LVDS bridge (U21.33)
SN65DSI83_SCL: 14 - MIPI to LVDS bridge (U21.15), 18 - I2C, XBee (R297.2)
SN65DSI83_SDA: 14 - MIPI to LVDS bridge (U21.16), 18 - I2C, XBee (R299.2)
SPI3_CS0: 05 - CCIMX8M Nano Digital interfaces (U5.C17), 10 - RS485, CAN (U10.13)
SPI3_SCK: 05 - CCIMX8M Nano Digital interfaces (U5.E17), 10 - RS485, CAN (U10.10)
SPI3_SDI: 05 - CCIMX8M Nano Digital interfaces (U5.C18), 10 - RS485, CAN (U10.12)
SPI3_SDO: 05 - CCIMX8M Nano Digital interfaces (U5.D18), 10 - RS485, CAN (U10.11)
SPKL_N: 17 - Audio (U29.22), 19 - Expansion connectors, User LEDs, RF signals (J53.8)
SPKL_P: 17 - Audio (U29.20), 19 - Expansion connectors, User LEDs, RF signals (J53.7)
SPKR_N: 17 - Audio (U29.15), 19 - Expansion connectors, User LEDs, RF signals (J53.10)
SPKR_P: 17 - Audio (U29.17), 19 - Expansion connectors, User LEDs, RF signals (J53.9)
SWD_CLK/PWR_IO: 03 - Power, reset (R1.1 R2.2), 04 - CCIMX8M Nano Power, Control, MCA (U5.AN24), 09 - JTAG, SWD, uSD, Mini PCIe, uSIM (J22.4 SWD.4)
SWD_DIO: 04 - CCIMX8M Nano Power, Control, MCA (U5.AN26), 09 - JTAG, SWD, uSD, Mini PCIe, uSIM (J22.2 SWD.2)
SYS_RESET: 03 - Power, reset (R5.2), 04 - CCIMX8M Nano Power, Control, MCA (U5.AN25), 09 - JTAG, SWD, uSD, Mini PCIe, uSIM (J22.10 SWD.10), 19 - Expansion connectors, User LEDs, RF signals (J43.3)
TXC_MAX98089: 13 - MIPI to HDMI bridge (R238.2), 17 - Audio (U29.8)
TXD_MAX98089: 13 - MIPI to HDMI bridge (R235.2), 17 - Audio (U29.9)
TXFS_MAX98089: 13 - MIPI to HDMI bridge (R240.2), 17 - Audio (U29.10)
UART3_CTS_B: 05 - CCIMX8M Nano Digital interfaces (U5.M29), 10 - RS485, CAN (R359.1), 19 - Expansion connectors, User LEDs, RF signals (J45.9)
UART3_RTS_B: 05 - CCIMX8M Nano Digital interfaces (U5.N29), 19 - Expansion connectors, User LEDs, RF signals (J45.7)
UART3_RX: 05 - CCIMX8M Nano Digital interfaces (U5.R1), 10 - RS485, CAN (R291.1), 19 - Expansion connectors, User LEDs, RF signals (J45.3)
UART3_TX: 05 - CCIMX8M Nano Digital interfaces (U5.P1), 10 - RS485, CAN (R292.1), 19 - Expansion connectors, User LEDs, RF signals (J45.1)
UART4_RX: 05 - CCIMX8M Nano Digital interfaces (U5.U29), 08 - Consoles (R153.1 R154.1)
UART4_TX: 05 - CCIMX8M Nano Digital interfaces (U5.T29), 08 - Consoles (R151.1 R152.1)
USB_HUB_N: 15 - USB HUB (U24.30), 16 - USB Recovery, USB OTG (R267.2 U28.7)
USB_HUB_P: 15 - USB HUB (U24.31), 16 - USB Recovery, USB OTG (R265.2 U28.3)
USB_HUB_RESET_N: 05 - CCIMX8M Nano Digital interfaces (U5.D17), 15 - USB HUB (C127.2 R250.1 R252.2 U24.26)
USB_OTG1_ID: 05 - CCIMX8M Nano Digital interfaces (U5.C6), 16 - USB Recovery, USB OTG (J35.4)
USB_OTG1_N: 05 - CCIMX8M Nano Digital interfaces (U5.A6), 16 - USB Recovery, USB OTG (R266.1 R267.1 U28.6)
USB_OTG1_P: 05 - CCIMX8M Nano Digital interfaces (U5.A7), 16 - USB Recovery, USB OTG (R263.1 R265.1 U28.4)
USB_OTG1_POWER: 05 - CCIMX8M Nano Digital interfaces (R353.1), 16 - USB Recovery, USB OTG (R350.2 U36.1)
USB_OTG1_VBUS: 05 - CCIMX8M Nano Digital interfaces (U5.B6), 16 - USB Recovery, USB OTG (R342.1 R354.1)
USB_OTG2_ID: 05 - CCIMX8M Nano Digital interfaces (U5.C10), 16 - USB Recovery, USB OTG (J34.4)
USB_OTG2_N: 05 - CCIMX8M Nano Digital interfaces (U5.A8), 16 - USB Recovery, USB OTG (L28.1)
USB_OTG2_P: 05 - CCIMX8M Nano Digital interfaces (U5.A9), 16 - USB Recovery, USB OTG (L28.4)
USB_OTG2_VBUS: 05 - CCIMX8M Nano Digital interfaces (U5.E7), 16 - USB Recovery, USB OTG (C142.2 C143.2 L27.2 U27.8)
USB_PCIe_D_N: 09 - JTAG, SWD, uSD, Mini PCIe, uSIM (J19.36), 15 - USB HUB (L25.3 U25.2)
USB_PCIe_D_P: 09 - JTAG, SWD, uSD, Mini PCIe, uSIM (J19.38), 15 - USB HUB (L25.2 U25.1)
USB_PWR: 05 - CCIMX8M Nano Digital interfaces (U5.C24), 15 - USB HUB (Q4.G R260.2)
USDHC2_CD_B: 05 - CCIMX8M Nano Digital interfaces (U5.G2), 09 - JTAG, SWD, uSD, Mini PCIe, uSIM (J18.9 J18.10 R158.2)
USDHC2_CLK: 05 - CCIMX8M Nano Digital interfaces (U5.L1), 09 - JTAG, SWD, uSD, Mini PCIe, uSIM (R161.1)
USDHC2_CMD: 05 - CCIMX8M Nano Digital interfaces (U5.F1), 09 - JTAG, SWD, uSD, Mini PCIe, uSIM (J18.3 R157.1)
USDHC2_DATA0: 05 - CCIMX8M Nano Digital interfaces (U5.G1), 09 - JTAG, SWD, uSD, Mini PCIe, uSIM (J18.7 R159.1)
USDHC2_DATA1: 05 - CCIMX8M Nano Digital interfaces (U5.H1), 09 - JTAG, SWD, uSD, Mini PCIe, uSIM (J18.8)
USDHC2_DATA2: 05 - CCIMX8M Nano Digital interfaces (U5.J1), 09 - JTAG, SWD, uSD, Mini PCIe, uSIM (J18.1)
USDHC2_DATA3: 05 - CCIMX8M Nano Digital interfaces (U5.K1), 09 - JTAG, SWD, uSD, Mini PCIe, uSIM (J18.2)
USER_BUTTON1: 04 - CCIMX8M Nano Power, Control, MCA (U5.AF29), 19 - Expansion connectors, User LEDs, RF signals (R320.1 SW3.3 SW3.4)
USER_BUTTON2: 05 - CCIMX8M Nano Digital interfaces (U5.F3), 19 - Expansion connectors, User LEDs, RF signals (R321.1 SW4.3 SW4.4)
USER_LED1: 04 - CCIMX8M Nano Power, Control, MCA (U5.AM25), 19 - Expansion connectors, User LEDs, RF signals (Q11.G R317.1)
USER_LED2: 04 - CCIMX8M Nano Power, Control, MCA (U5.AM23), 19 - Expansion connectors, User LEDs, RF signals (Q12.G R318.1)
USER_LED3: 05 - CCIMX8M Nano Digital interfaces (U5.E4), 19 - Expansion connectors, User LEDs, RF signals (Q13.G R319.1)
VCC_LICELL: 03 - Power, reset (D2.A R349.1), 04 - CCIMX8M Nano Power, Control, MCA (U5.AM8)
WLAN_LED: 06 - CCIMX8M Nano RF, PCIe (U5.F24), 19 - Expansion connectors, User LEDs, RF signals (J49.15)
WLAN_SD1_CLK: 06 - CCIMX8M Nano RF, PCIe (R40.2), 19 - Expansion connectors, User LEDs, RF signals (J49.17)
WLAN_SD1_CMD: 06 - CCIMX8M Nano RF, PCIe (R41.2), 19 - Expansion connectors, User LEDs, RF signals (J49.19)
WLAN_SD1_D0: 06 - CCIMX8M Nano RF, PCIe (R43.2), 19 - Expansion connectors, User LEDs, RF signals (J49.2)
WLAN_SD1_D1: 06 - CCIMX8M Nano RF, PCIe (R44.2), 19 - Expansion connectors, User LEDs, RF signals (J49.4)
WLAN_SD1_D2: 06 - CCIMX8M Nano RF, PCIe (R45.2), 19 - Expansion connectors, User LEDs, RF signals (J49.6)
WLAN_SD1_D3: 06 - CCIMX8M Nano RF, PCIe (R47.2), 19 - Expansion connectors, User LEDs, RF signals (J49.8)
WLAN_SD1_D4: 06 - CCIMX8M Nano RF, PCIe (R48.2), 19 - Expansion connectors, User LEDs, RF signals (J49.10)
WLAN_SD1_D5: 06 - CCIMX8M Nano RF, PCIe (R49.2), 19 - Expansion connectors, User LEDs, RF signals (J49.12)
WLAN_SD1_D6: 06 - CCIMX8M Nano RF, PCIe (R50.2), 19 - Expansion connectors, User LEDs, RF signals (J49.14)
WLAN_SD1_D7: 06 - CCIMX8M Nano RF, PCIe (R52.2), 19 - Expansion connectors, User LEDs, RF signals (J49.16)
WLAN_SDIO_INT_L: 06 - CCIMX8M Nano RF, PCIe (U5.G18), 19 - Expansion connectors, User LEDs, RF signals (J49.13)
WOL_INT: 05 - CCIMX8M Nano Digital interfaces (U5.Y1), 11 - Ethernet (R181.2 U15.40)
XBEE1_ON/SLEEP_N: 04 - CCIMX8M Nano Power, Control, MCA (U5.AL24), 18 - I2C, XBee (J40.8)
XBEE1_RESET_N: 04 - CCIMX8M Nano Power, Control, MCA (U5.AL25), 18 - I2C, XBee (J39.5)
XBEE1_SLEEP_RQ: 04 - CCIMX8M Nano Power, Control, MCA (U5.AM26), 18 - I2C, XBee (J39.9)
XBEE1_UART_CTS: 04 - CCIMX8M Nano Power, Control, MCA (U5.AN23), 18 - I2C, XBee (R336.2), 19 - Expansion connectors, User LEDs, RF signals (J45.10)
XBEE1_UART_RTS: 04 - CCIMX8M Nano Power, Control, MCA (U5.AL27), 18 - I2C, XBee (R307.2 R335.2), 19 - Expansion connectors, User LEDs, RF signals (J45.8)
XBEE1_UART_RX: 04 - CCIMX8M Nano Power, Control, MCA (U5.AN22), 18 - I2C, XBee (R333.1), 19 - Expansion connectors, User LEDs, RF signals (J45.4)
XBEE1_UART_TX: 04 - CCIMX8M Nano Power, Control, MCA (U5.AN21), 18 - I2C, XBee (R334.1), 19 - Expansion connectors, User LEDs, RF signals (J45.2)
XBEE1_USB_D_N: 15 - USB HUB (L26.2 U25.4), 18 - I2C, XBee (J39.8)
XBEE1_USB_D_P: 15 - USB HUB (L26.3 U25.5), 18 - I2C, XBee (J39.7)
XBEE2_ON/SLEEP_N: 05 - CCIMX8M Nano Digital interfaces (U5.AG12), 18 - I2C, XBee (J42.8)
XBEE2_RESET_N: 05 - CCIMX8M Nano Digital interfaces (U5.AG11), 18 - I2C, XBee (J41.5)
XBEE2_SLEEP_RQ: 05 - CCIMX8M Nano Digital interfaces (U5.AG9), 18 - I2C, XBee (J41.9)
XBEE2_UART_CTS: 05 - CCIMX8M Nano Digital interfaces (U5.E22), 18 - I2C, XBee (J42.5 R312.2)
XBEE2_UART_RTS: 05 - CCIMX8M Nano Digital interfaces (U5.E19), 18 - I2C, XBee (J42.9)
XBEE2_UART_RX: 08 - Consoles (R154.2), 18 - I2C, XBee (J41.2)
XBEE2_UART_TX: 08 - Consoles (R152.2), 18 - I2C, XBee (J41.3)

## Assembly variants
55002060-01: not fitted C11 C141 C142 C143 C147 C174 C176 C194 C195 C196 D2 D9 D21 J2 J3 J5 J6 J7 J8 J9 J10 J11 J12 J17 J20 J22 J28 J30 J34 J36 J43 J44 J45 J46 J47 J48 J49 J50 J52 J53 L27 L28 L29 L33 L38 L40 R4 R6 R8 R23 R36 R40 R41 R43 R44 R45 R47 R48 R49 R50 R51 R52 R53 R54 R55 R56 R57 R58 R59 R61 R62 R81 R83 R87 R88 R89 R91 R92 R93 R94 R95 R97 R99 R100 R101 R102 R106 R112 R114 R118 R119 R122 R124 R126 R127 R128 R130 R132 R133 R134 R151 R153 R156 R162 R163 R170 R175 R184 R186 R187 R188 R189 R190 R191 R192 R193 R205 R207 R209 R211 R213 R215 R217 R219 R221 R223 R236 R239 R241 R244 R245 R252 R257 R261 R263 R265 R266 R267 R275 R278 R282 R304 R305 R306 R307 R308 R309 R310 R311 R312 R313 R321 R322 R326 R327 R328 R329 R330 R332 R338 R340 R342 R344 R345 R346 R349 R350 R351 R353 R356 R363 U27 U36; alternate parts R224 -> 1000537, U20 -> 1002785, C22 -> 1001303
55002060-02: not fitted C11 C147 C174 C176 C194 C195 C196 D2 D21 J2 J3 J5 J6 J7 J8 J9 J10 J11 J12 J17 J20 J22 J28 J30 J36 J43 J44 J45 J46 J47 J48 J49 J50 J52 J53 L33 L38 L40 R4 R6 R8 R23 R36 R40 R41 R43 R44 R45 R47 R48 R49 R50 R51 R52 R53 R54 R55 R56 R57 R58 R59 R61 R62 R81 R83 R86 R87 R88 R89 R91 R92 R93 R94 R95 R97 R99 R100 R101 R102 R103 R106 R107 R112 R114 R118 R119 R122 R124 R125 R127 R128 R130 R132 R133 R134 R151 R153 R156 R162 R163 R170 R175 R186 R187 R188 R189 R190 R191 R192 R193 R205 R207 R209 R211 R213 R215 R217 R219 R221 R223 R236 R239 R241 R244 R245 R252 R257 R263 R265 R266 R267 R275 R278 R282 R304 R305 R306 R307 R308 R309 R310 R311 R312 R313 R321 R322 R326 R327 R328 R329 R330 R332 R338 R340 R342 R344 R345 R346 R349 R350 R351 R353 R356 R363 U36; alternate parts R224 -> 1000537, U20 -> 1002785, C22 -> 1001303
